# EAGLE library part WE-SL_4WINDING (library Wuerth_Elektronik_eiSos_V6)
SMD Common-Mode Choke Line Filter WE-SL For distortion-free removal of noise from transmitted electrical signals - 2 or 4 winding configuration - Offering a wide band width with the core materials of NiZn and MnZn -- Current compensated choke for data and signal lines -- USB/CAN/ISDN-Bus -- Power supply systems -- Control lines -- LAN, PBX, cable TV, CD-ROM, 8mm video, etc.

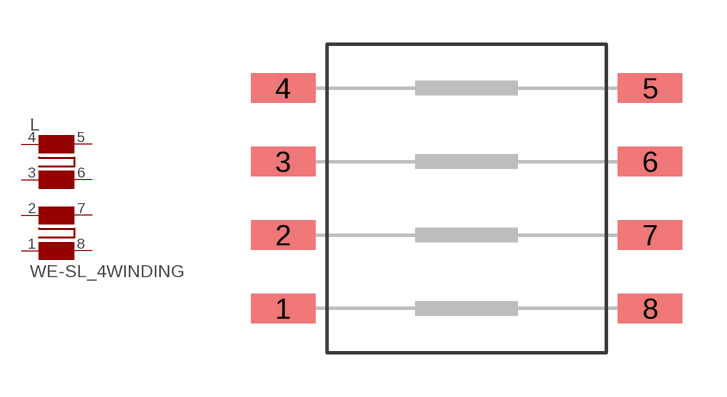
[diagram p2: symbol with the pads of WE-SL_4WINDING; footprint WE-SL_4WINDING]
Designator prefix L

## WE-SL_4WINDING  [WE-SL_4WINDING]
1  4  pas
2  3  pas
3  2  pas
4  1  pas
5  8  pas
6  7  pas
7  6  pas
8  5  pas

## Footprint WE-SL_4WINDING (pad centres in mm)
SMD Common-Mode Line Filter WE-SL
smd 2.2 x 1: 1 -6.25,-3.75; 2 -6.25,-1.25; 3 -6.25,1.25; 4 -6.25,3.75; 5 6.25,3.75; 6 6.25,1.25; 7 6.25,-1.25; 8 6.25,-3.75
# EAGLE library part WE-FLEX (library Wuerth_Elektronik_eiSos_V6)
FLEX-Transformer WE-FLEX Transformer with 6 windings - 4 sizes with 5 different lengths of air gap each - Insulation voltage 500 VDC - Low leakage inductance -- By using different circuits more than 300 transformer solutions and about 100 choke solution possible -- For all kinds of switching regulators: Flyback converters, Forward converters, Push- pull converters, SEPIC converter

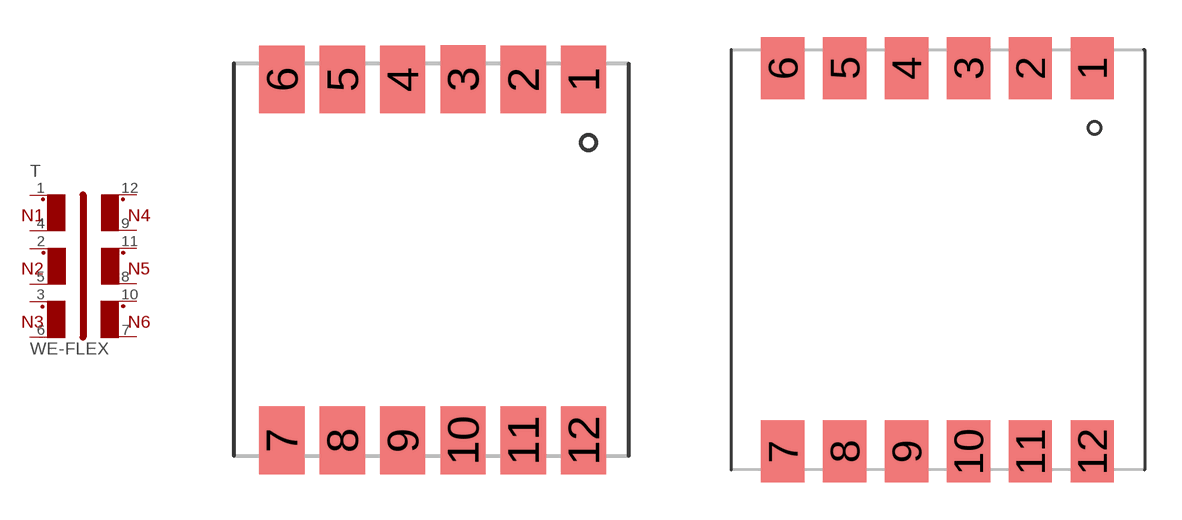
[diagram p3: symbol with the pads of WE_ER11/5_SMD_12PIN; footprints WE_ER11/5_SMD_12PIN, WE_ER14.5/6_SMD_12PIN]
Designator prefix T

## WE-FLEX_ER11/5  [WE_ER11/5_SMD_12PIN]
1  1  pas
2  3  pas
3  5  pas
4  2  pas
5  4  pas
6  6  pas
7  12  pas
8  10  pas
9  8  pas
10  11  pas
11  9  pas
12  7  pas

## WE-FLEX_ER14.5/6  [WE_ER14.5/6_SMD_12PIN]
Pads as for WE_ER11/5_SMD_12PIN

## WE-FLEX_EFD15  [WE_EFD15_SMD_12PIN]
1  1  pas
2  3  pas
3  5  pas
4  7  pas
5  9  pas
6  11  pas
7  12  pas
8  10  pas
9  8  pas
10  6  pas
11  4  pas
12  2  pas

## WE-FLEX_EFD20  [WE_EFD20_SMD_12PIN]
Pads as for WE_EFD15_SMD_12PIN

## Footprint WE_ER11/5_SMD_12PIN (pad centres in mm)
Transformer, ER11/5 SMD 12Pin
smd 1.5 x 2.25: 1 4.92,5.9; 2 2.92,5.9; 3 0.92,5.91; 4 -1.08,5.9; 5 -3.08,5.9; 6 -5.08,5.9; 7 -5.08,-6.07; 8 -3.08,-6.07; 9 -1.08,-6.07; 10 0.92,-6.07; 11 2.92,-6.07; 12 4.92,-6.07

## Footprint WE_ER14.5/6_SMD_12PIN (pad centres in mm)
Transformer, ER14.5/6 SMD 12Pin
smd 1.75 x 2.5: 1 6.26,7.75; 2 3.76,7.75; 3 1.26,7.75; 4 -1.24,7.75; 5 -3.74,7.75; 6 -6.24,7.75; 7 -6.24,-7.75; 8 -3.74,-7.75; 9 -1.24,-7.75; 10 1.26,-7.75; 11 3.76,-7.75; 12 6.26,-7.75

## Footprint WE_EFD15_SMD_12PIN (pad centres in mm)
Transformer, EFD15 SMD 12 Pin
smd 2.62 x 1.17: 1 -9.895,6.225; 2 -9.895,3.735; 3 -9.895,1.245; 4 -9.895,-1.245; 5 -9.895,-3.735; 6 -9.895,-6.225; 7 9.895,-6.225; 8 9.895,-3.735; 9 9.895,-1.245; 10 9.895,1.245; 11 9.895,3.735; 12 9.895,6.225

## Footprint WE_EFD20_SMD_12PIN (pad centres in mm)
Transformer, EFD20 SMD 12 Pin
smd 3.05 x 1.27: 1 -13.26,7.5; 2 -13.26,4.5; 3 -13.26,1.5; 4 -13.26,-1.5; 5 -13.26,-4.5; 6 -13.26,-7.5; 7 13.26,-7.5; 8 13.26,-4.5; 9 13.26,-1.5; 10 13.26,1.5; 11 13.26,4.5; 12 13.26,7.5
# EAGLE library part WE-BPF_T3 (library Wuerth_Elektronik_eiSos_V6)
SMD-Multilayer Chip Band-Pass Filter WE-BPF - low insertion loss - High attenuation - Guaranteed filter characteristics over a wide temperature range -- Rf applications in the frequency range up to 6GHz -- Wireless communcation systems like DECT, PACS, PHS, GSM,WLAN,Bluetooth,..

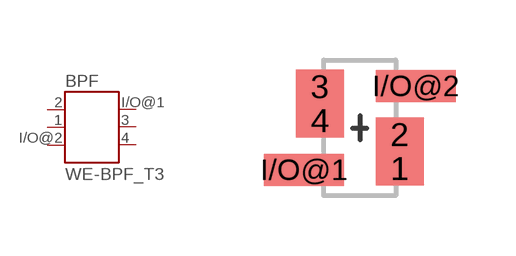
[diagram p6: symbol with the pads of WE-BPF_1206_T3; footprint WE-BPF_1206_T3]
Designator prefix BPF

## WE-BPF_T3_1206_T3  [WE-BPF_1206_T3]
1  GND  pas
2  GND  pas
3  GND  pas
4  GND  pas
I/O@1  I/O  pas
I/O@2  I/O  pas

## Footprint WE-BPF_1206_T3 (pad centres in mm)
Multilayer Chip Band -Pass Filter WE-BPF
smd 1.2 x 0.85: 1 1,-1.02; 2 1,-0.17; 3 -1,1.03; 4 -1,0.18
smd 2 x 0.8: I/O@1 -1.4,-1.05; I/O@2 1.4,1.05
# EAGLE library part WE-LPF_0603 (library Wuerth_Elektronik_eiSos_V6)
Multilayer Chip Low-Pass Filters WE-LPF SMD 0603 - One inductor and three capacitors or two inductors and five capacitors in one component - Power capacity up to 3W - Low insertion loss and high attenuation in the stop-band -- RF-applications in the area of 0.8 to 6 GHz -- wireless communication systems like DECT,PACS,PHS,GSM, Bluetooth,...

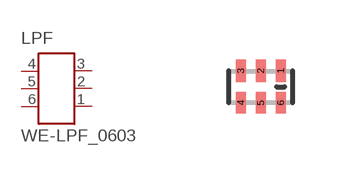
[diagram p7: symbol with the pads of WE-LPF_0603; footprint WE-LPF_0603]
Designator prefix LPF

## WE-LPF_0603  [WE-LPF_0603]
1  GND  pwr
2  NC  nc
3  GND  pwr
4  OUT  out
5  GND  pwr
6  IN  in

## Footprint WE-LPF_0603 (pad centres in mm)
Multilayer Chip Low-Pass Filters WE-LPF
smd 0.25 x 0.55: 1 0.5,0.4; 2 0,0.4; 3 -0.5,0.4; 4 -0.5,-0.4; 5 0,-0.4; 6 0.5,-0.4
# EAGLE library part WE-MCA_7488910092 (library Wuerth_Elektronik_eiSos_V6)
Multilayer Chip Antenna WE-MCA - SMD Multilayer Chip Antenna - Extremely low profile - Very light component - Operating temperature: -40°C to +85°C - Power capacity: 3 W max. - Omni-directional -- For RF application in the area of 2,4 GHz -- WLAN -- Home RF (868 MHz) -- Bluetooth applications -- IEEE 802.11a/b -- GPS -- GSM -- WIMAX applications

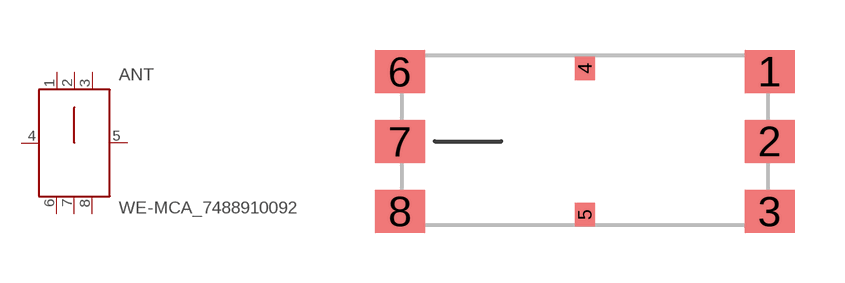
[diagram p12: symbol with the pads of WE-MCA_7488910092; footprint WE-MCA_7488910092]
Designator prefix ANT

## WE-MCA_7488910092  [WE-MCA_7488910092]
1  NC  nc
2  FD  pas
3  NC  nc
4  NC  nc
5  NC  nc
6  NC  nc
7  NC  nc
8  NC  nc

## Footprint WE-MCA_7488910092 (pad centres in mm)
Multilayer Chip Antenna WE-MCA
smd 1.5 x 1.3: 1 5.55,2.1; 2 5.55,0; 3 5.55,-2.1; 6 -5.55,2.1; 7 -5.55,0; 8 -5.55,-2.1
smd 0.6 x 0.7: 4 0,2.2; 5 0,-2.2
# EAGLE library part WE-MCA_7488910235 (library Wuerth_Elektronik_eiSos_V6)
Multilayer Chip Antenna WE-MCA - SMD Multilayer Chip Antenna - Extremely low profile - Very light component - Operating temperature: -40°C to +85°C - Power capacity: 3 W max. - Omni-directional -- For RF application in the area of 2,4 GHz -- WLAN -- Home RF (868 MHz) -- Bluetooth applications -- IEEE 802.11a/b -- GPS -- GSM -- WIMAX applications

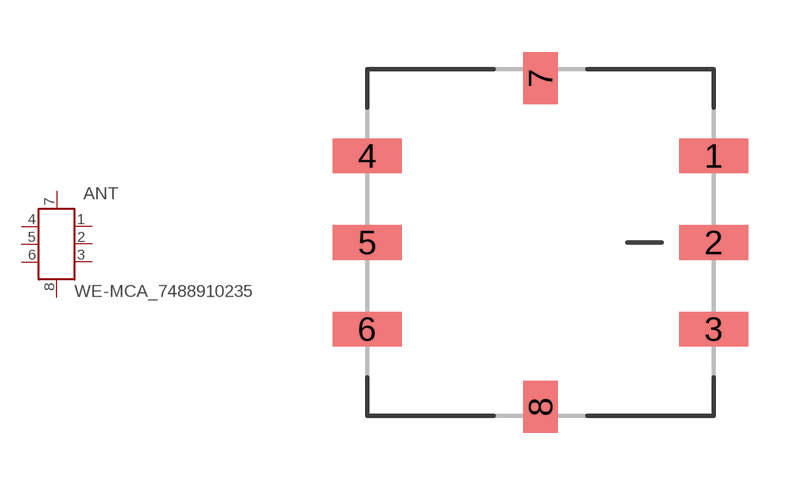
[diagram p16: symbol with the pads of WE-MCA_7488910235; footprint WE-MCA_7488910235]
Designator prefix ANT

## WE-MCA_7488910235  [WE-MCA_7488910235]
1  GND  pwr
2  FD  pas
3  GND  pwr
4  NC  nc
5  NC  nc
6  NC  nc
7  NC  nc
8  NC  nc

## Footprint WE-MCA_7488910235 (pad centres in mm)
Multilayer Chip Antenna WE-MCA
smd 2 x 1: 1 5,2.5; 2 5,0; 3 5,-2.5; 4 -5,2.5; 5 -5,0; 6 -5,-2.5
smd 1 x 1.5: 7 0,4.75; 8 0,-4.75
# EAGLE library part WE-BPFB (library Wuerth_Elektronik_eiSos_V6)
Multilayer SMD Band-Pass Filter with Balun WE-BPFB - Low insertion loss - High attenuation in the stop zone - Impedance ration 50:100 - Power capacity: 1 W max. - Operating temperature: -40°C up to +85°C -- 2,4 GHz WLAN -- Home RF -- Bluetooth

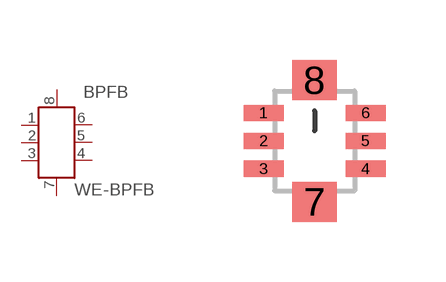
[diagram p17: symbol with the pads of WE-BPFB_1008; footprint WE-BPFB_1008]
Designator prefix BPFB

## WE-BPFB_1008  [WE-BPFB_1008]
1  NC  nc
2  UNBAL.P  pas
3  NC/DC  pas
4  BAL.P  pas
5  NC  nc
6  BAL.P  pas
7  GND  pas
8  GND  pas

## Footprint WE-BPFB_1008 (pad centres in mm)
Multilayer SMD Band-Pass Filter with Balun WE-BPFB
smd 1 x 0.4: 1 -1.275,0.7; 2 -1.275,0; 3 -1.275,-0.7; 4 1.275,-0.7; 5 1.275,0; 6 1.275,0.7
smd 1.1 x 1: 7 0,-1.525; 8 0,1.525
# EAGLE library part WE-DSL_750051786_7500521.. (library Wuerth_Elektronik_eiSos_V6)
SMD-ADSL Transformer WE-DSL - IEC60950 compatible -- for ADSL applications -- Matched to various manufacturers ADSL ICs

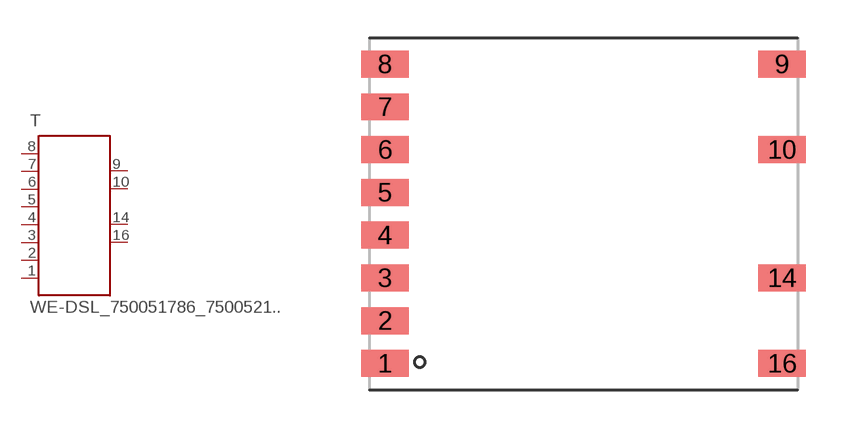
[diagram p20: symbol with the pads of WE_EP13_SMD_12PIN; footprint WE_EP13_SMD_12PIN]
Designator prefix T

## WE-DSL_750051786_7500521..  [WE_EP13_SMD_12PIN]
1  1  pas
2  2  pas
3  3  pas
4  4  pas
5  5  pas
6  6  pas
7  7  pas
8  8  pas
9  9  pas
10  10  pas
14  11  pas
16  12  pas

## Footprint WE_EP13_SMD_12PIN (pad centres in mm)
Transformer, EP13 SMD 12 Pin
smd 1.88 x 1.07: 1 -7.885,-5.95; 2 -7.885,-4.25; 3 -7.885,-2.55; 4 -7.885,-0.85; 5 -7.885,0.85; 6 -7.885,2.55; 7 -7.885,4.25; 8 -7.885,5.95; 9 7.885,5.95; 10 7.885,2.55; 14 7.885,-2.55; 16 7.885,-5.95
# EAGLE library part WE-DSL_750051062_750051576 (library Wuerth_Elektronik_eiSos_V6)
SMD-HDSL Transformer WE-DSL - IEC60950 compatible -- for HDSL applications -- Matched to various manufacturers HDSL ICs

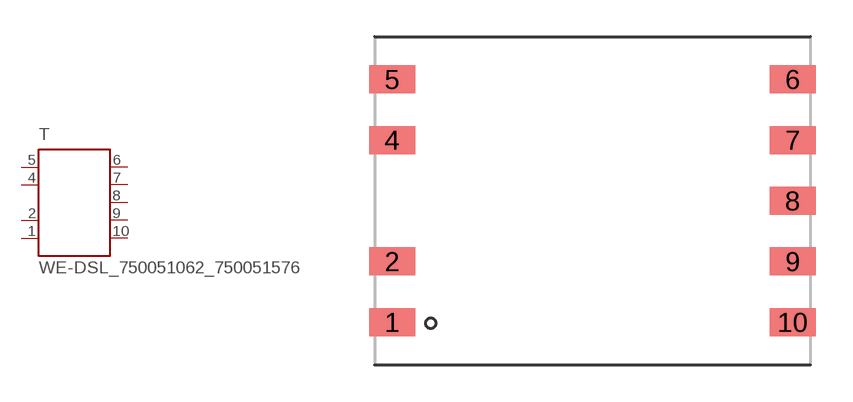
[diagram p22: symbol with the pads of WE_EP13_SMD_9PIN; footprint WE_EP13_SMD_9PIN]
Designator prefix T

## WE-DSL_750051062_750051576  [WE_EP13_SMD_9PIN]
1  1  pas
2  2  pas
4  4  pas
5  5  pas
6  6  pas
7  7  pas
8  8  pas
9  9  pas
10  10  pas

## Footprint WE_EP13_SMD_9PIN (pad centres in mm)
SMD-xDSL Transformer WE-DSL
smd 1.88 x 1.143: 1 -8.18,-4.96; 2 -8.18,-2.48; 4 -8.18,2.48; 5 -8.18,4.96; 6 8.18,4.96; 7 8.18,2.48; 8 8.18,0; 9 8.18,-2.48; 10 8.18,-4.96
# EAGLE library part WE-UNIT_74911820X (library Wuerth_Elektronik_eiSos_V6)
Off-Line Transformer WE-Unit - Nominal input voltage: 85-265 VAC - Output power 9 W - Operating temperature: -40°C to +125 °C - Clearance and creepage distance 6 mm min. - Isolation voltage 4 kVAC -- Designed for Tiny switch ICs from power integration and NCP101x or 105x of Semiconductor -- Universal input -- Offline-switch mode power supplies

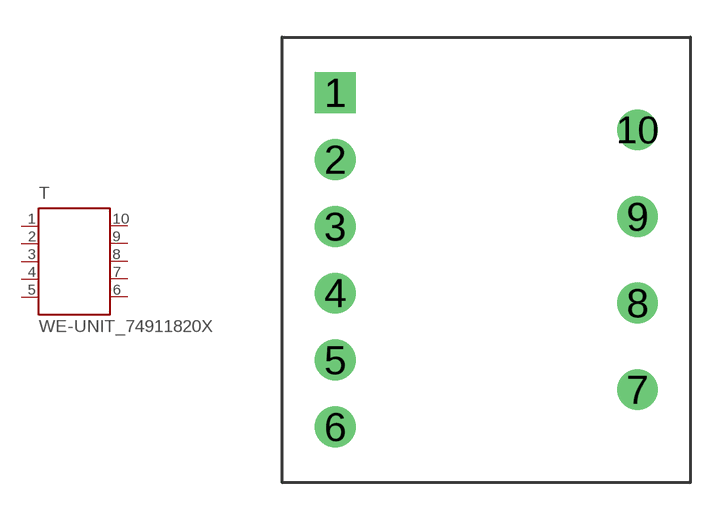
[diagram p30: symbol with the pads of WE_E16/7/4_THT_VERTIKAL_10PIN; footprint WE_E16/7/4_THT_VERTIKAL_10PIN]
Designator prefix T

## WE-UNIT_74911820X  [WE_E16/7/4_THT_VERTIKAL_10PIN]
1  1  pas
2  2  pas
3  3  pas
4  4  pas
5  5  pas
6  6  pas
7  7  pas
8  8  pas
9  9  pas
10  10  pas

## Footprint WE_E16/7/4_THT_VERTIKAL_10PIN (pad centres in mm)
Transformer, E16/7/4 THT Vertikal 10 Pin
drill 1.1 square: 1 -6.1,6.75
drill 1.1: 2 -6.1,4.05; 3 -6.1,1.35; 4 -6.1,-1.35; 5 -6.1,-4.05; 6 -6.1,-6.75; 7 6.1,-5.25; 8 6.1,-1.75; 9 6.1,1.75; 10 6.1,5.25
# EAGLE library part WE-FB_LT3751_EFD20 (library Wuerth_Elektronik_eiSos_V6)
Flyback Converter WE-FB for LT3751 - designd for LT3751

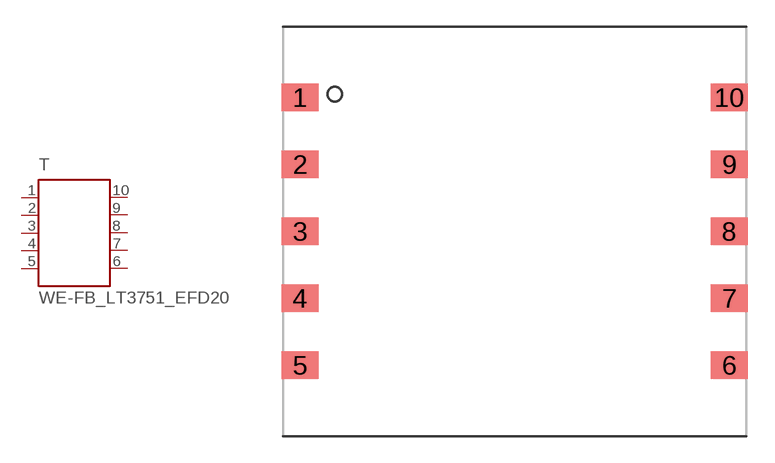
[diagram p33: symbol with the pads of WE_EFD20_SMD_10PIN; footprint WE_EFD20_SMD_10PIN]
Designator prefix T

## WE-FB_LT3751_EFD20  [WE_EFD20_SMD_10PIN]
1  1  pas
2  2  pas
3  3  pas
4  4  pas
5  5  pas
6  6  pas
7  7  pas
8  8  pas
9  9  pas
10  10  pas

## Footprint WE_EFD20_SMD_10PIN (pad centres in mm)
Transformer, EFD20 SMD 10 Pin
smd 2.08 x 1.55: 1 -12.05,7.52; 2 -12.05,3.76; 3 -12.05,0; 4 -12.05,-3.76; 5 -12.05,-7.52; 6 12.05,-7.52; 7 12.05,-3.76; 8 12.05,0; 9 12.05,3.76; 10 12.05,7.52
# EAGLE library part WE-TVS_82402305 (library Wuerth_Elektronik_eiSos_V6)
TVS Diode Array WE-TVS, Standard Series - Low capazity - No leakage current - Low clamping voltage - high ESD voltage protection - Uni- and bidirectional protection -- DC Distribution -- Headsets and Accessoires -- PDAs -- Digital Cameras -- MP3-Players -- Touch Panels

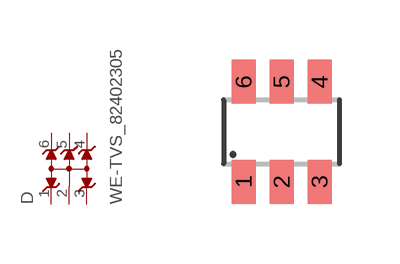
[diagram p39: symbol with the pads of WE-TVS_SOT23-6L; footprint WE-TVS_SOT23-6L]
Designator prefix D

## WE-TVS_82402305  [WE-TVS_SOT23-6L]
1  1  pas
2  GND  pwr
3  2  pas
4  3  pas
5  4  pas
6  5  pas

## Footprint WE-TVS_SOT23-6L (pad centres in mm)
TVS Diode Array WE-TVS
smd 0.6 x 1.1: 1 -0.95,-1.25; 2 0,-1.25; 3 0.95,-1.25; 4 0.95,1.25; 5 0,1.25; 6 -0.95,1.25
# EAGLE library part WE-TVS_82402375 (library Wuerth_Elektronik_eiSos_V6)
TVS Diode Array WE-TVS, Standard Series - Low capazity - No leakage current - Low clamping voltage - high ESD voltage protection - Uni- and bidirectional protection -- DC Distribution -- Headsets and Accessoires -- PDAs -- Digital Cameras -- MP3-Players -- Touch Panels

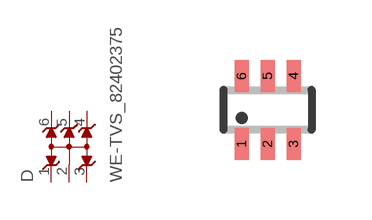
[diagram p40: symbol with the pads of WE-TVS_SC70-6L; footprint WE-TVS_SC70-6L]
Designator prefix D

## WE-TVS_82402375  [WE-TVS_SC70-6L]
1  1  pas
2  GND  pwr
3  2  pas
4  3  pas
5  4  pas
6  5  pas

## Footprint WE-TVS_SC70-6L (pad centres in mm)
TVS Diode Array WE-TVS
smd 0.35 x 0.8: 1 -0.65,-0.85; 2 0,-0.85; 3 0.65,-0.85; 4 0.65,0.85; 5 0,0.85; 6 -0.65,0.85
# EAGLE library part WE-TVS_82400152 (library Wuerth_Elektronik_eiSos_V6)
TVS Diode Array WE-TVS, High Speed Series - Low capazity - No leakage current - Low clamping voltage - high ESD voltage protection -- USB 1.0 - 2.0 Flow Thru Design

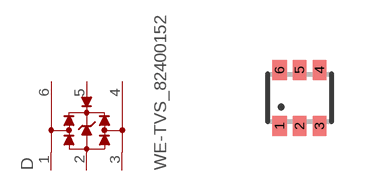
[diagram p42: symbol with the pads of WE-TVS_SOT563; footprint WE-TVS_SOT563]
Designator prefix D

## WE-TVS_82400152  [WE-TVS_SOT563]
1  1  pas
2  GND  pwr
3  2  pas
4  3  pas
5  VDD  pwr
6  4  pas

## Footprint WE-TVS_SOT563 (pad centres in mm)
TVS Diode Array WE-TVS
smd 0.35 x 0.5: 1 -0.5,-0.7; 2 0,-0.7; 3 0.5,-0.7; 4 0.5,0.7; 5 0,0.7; 6 -0.5,0.7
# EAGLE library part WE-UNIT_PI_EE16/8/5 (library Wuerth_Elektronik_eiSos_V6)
Off-Line Transformer WE-Unit PI - Nominal input voltage: 85-265 VAC - Output power from 2 W to 5 W - Operating temperature: -40°C to +125 °C - Clearance and creepage distance 6 mm min. - Isolation voltage 4 kVAC -- Especially designed for several ICs from Power Integrations -- Universal input -- Offline-switch mode power supplies

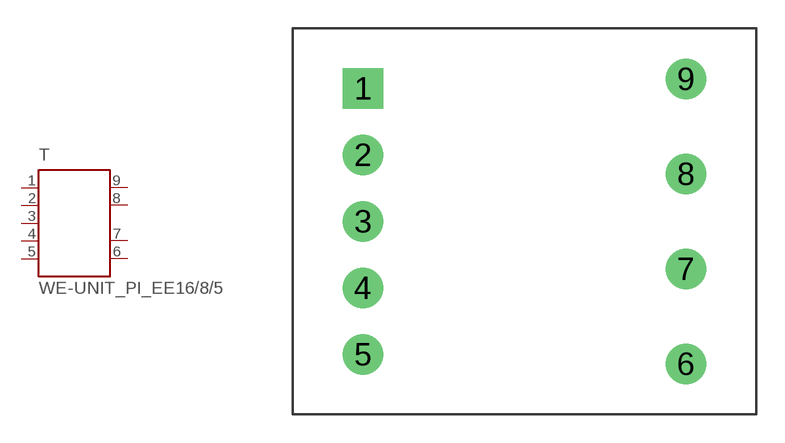
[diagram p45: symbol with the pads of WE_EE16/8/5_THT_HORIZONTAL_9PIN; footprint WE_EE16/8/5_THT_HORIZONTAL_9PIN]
Designator prefix T

## WE-UNIT_PI_EE16/8/5  [WE_EE16/8/5_THT_HORIZONTAL_9PIN]
1  5  pas
2  4  pas
3  3  pas
4  2  pas
5  1  pas
6  9  pas
7  8  pas
8  7  pas
9  6  pas

## Footprint WE_EE16/8/5_THT_HORIZONTAL_9PIN (pad centres in mm)
Transformer, EE16/8/5 THT Horizontal 9 Pin
drill 1.42 square: 1 -8.5,7
drill 1.42: 2 -8.5,3.5; 3 -8.5,0; 4 -8.5,-3.5; 5 -8.5,-7; 6 8.5,-7.5; 7 8.5,-2.5; 8 8.5,2.5; 9 8.5,7.5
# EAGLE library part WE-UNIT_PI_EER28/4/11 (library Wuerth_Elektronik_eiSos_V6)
Off-Line Transformer WE-Unit PI - Nominal input voltage: 85-265 VAC - Output power 34.4 W - Operating temperature: -40°C to +125 °C - Clearance and creepage distance 6 mm min. - Isolation voltage 4 kVAC -- Especially designed for several ICs from Power Integrations TOP258 -- Universal input -- Offline-switch mode power supplies

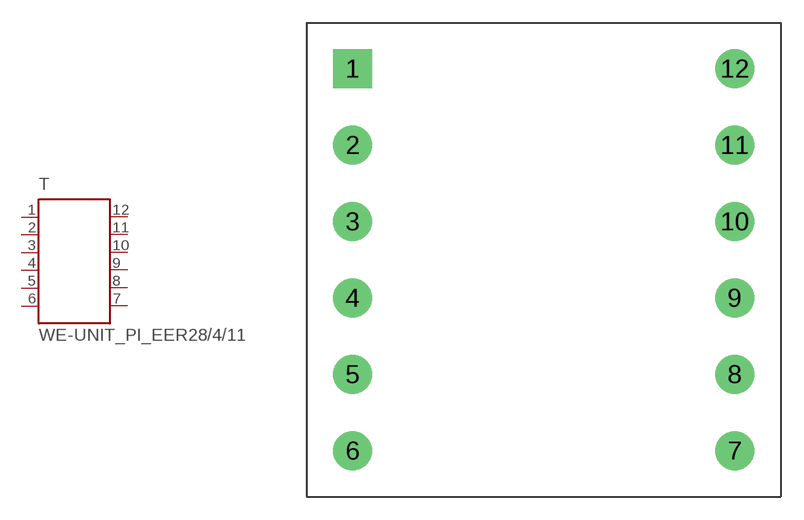
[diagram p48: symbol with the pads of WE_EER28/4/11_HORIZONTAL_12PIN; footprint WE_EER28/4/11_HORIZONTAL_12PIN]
Designator prefix T

## WE-UNIT_PI_EER28/4/11  [WE_EER28/4/11_HORIZONTAL_12PIN]
1  1  pas
2  2  pas
3  3  pas
4  4  pas
5  5  pas
6  6  pas
7  7  pas
8  8  pas
9  9  pas
10  10  pas
11  11  pas
12  12  pas

## Footprint WE_EER28/4/11_HORIZONTAL_12PIN (pad centres in mm)
Transformer, EER 28/4/11 THT Horizontal 12Pin
drill 1.69 square: 1 -12.5,12.5
drill 1.69: 2 -12.5,7.5; 3 -12.5,2.5; 4 -12.5,-2.5; 5 -12.5,-7.5; 6 -12.5,-12.5; 7 12.5,-12.5; 8 12.5,-7.5; 9 12.5,-2.5; 10 12.5,2.5; 11 12.5,7.5; 12 12.5,12.5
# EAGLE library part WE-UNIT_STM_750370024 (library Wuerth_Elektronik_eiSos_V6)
Off-Line Transformer WE-Unit STM - Nominal input voltage: 85-265 VAC - Operating temperature: -40°C to +125 °C - Isolation voltage 4 kVAC -- Especially designed for several ICs from STMicroelectronics VIPer 17H -- Universal input -- Offline-switch mode power supplies

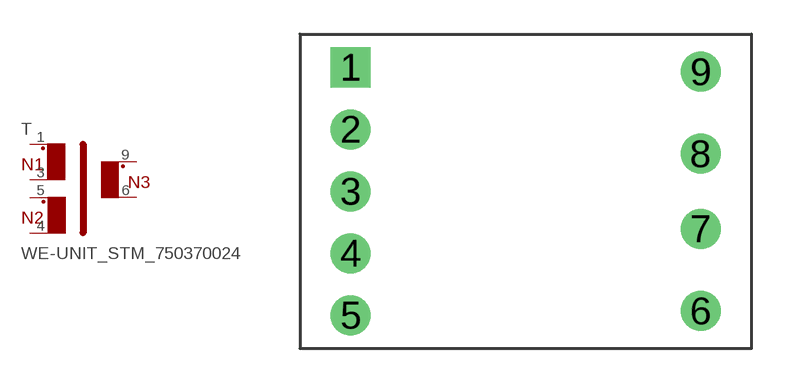
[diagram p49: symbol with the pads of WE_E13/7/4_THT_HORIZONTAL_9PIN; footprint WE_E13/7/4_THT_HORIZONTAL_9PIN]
Designator prefix T

## WE-UNIT_STM_750370024  [WE_E13/7/4_THT_HORIZONTAL_9PIN]
1  1  pas
3  2  pas
4  4  pas
5  3  pas
6  5  pas
9  6  pas

## Footprint WE_E13/7/4_THT_HORIZONTAL_9PIN (pad centres in mm)
Transformer, E13/7/4 THT Horizontal 9 Pin
drill 1.17 square: 1 -7.675,5.44
drill 1.17: 2 -7.675,2.72; 3 -7.675,0; 4 -7.675,-2.72; 5 -7.675,-5.44; 6 7.675,-5.25; 7 7.675,-1.65; 8 7.675,1.65; 9 7.675,5.25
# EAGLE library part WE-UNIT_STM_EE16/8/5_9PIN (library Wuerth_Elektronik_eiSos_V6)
Off-Line Transformer WE-Unit STM - Nominal input voltage: 85-265 VAC - Operating temperature: -40°C to +125 °C - Isolation voltage 4 kVAC -- Especially designed for several ICs from STMicroelectronics VIPer 17L and VIPer 15L -- Universal input -- Offline-switch mode power supplies

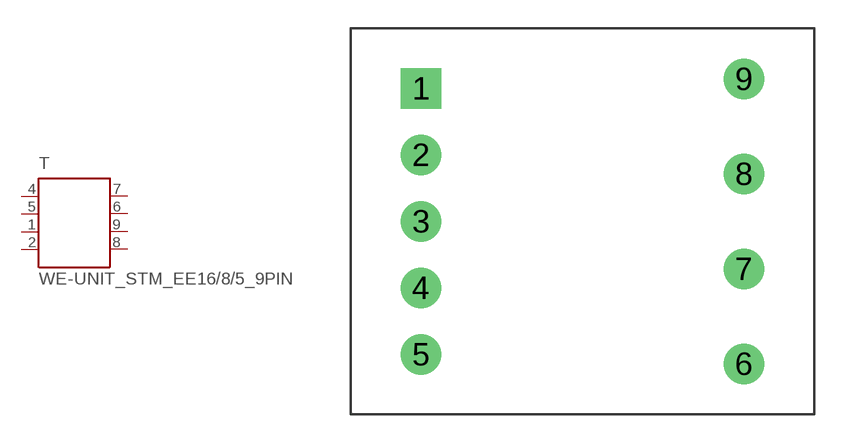
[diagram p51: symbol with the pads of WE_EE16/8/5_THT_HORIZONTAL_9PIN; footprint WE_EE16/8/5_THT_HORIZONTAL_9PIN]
Designator prefix T

## WE-UNIT_STM_EE16/8/5_9PIN  [WE_EE16/8/5_THT_HORIZONTAL_9PIN]
1  2  pas
2  1  pas
4  4  pas
5  3  pas
6  6  pas
7  5  pas
8  8  pas
9  7  pas

## Footprint WE_EE16/8/5_THT_HORIZONTAL_9PIN (pad centres in mm)
Transformer, EE16/8/5 THT Horizontal 9 Pin
drill 1.42 square: 1 -8.5,7
drill 1.42: 2 -8.5,3.5; 3 -8.5,0; 4 -8.5,-3.5; 5 -8.5,-7; 6 8.5,-7.5; 7 8.5,-2.5; 8 8.5,2.5; 9 8.5,7.5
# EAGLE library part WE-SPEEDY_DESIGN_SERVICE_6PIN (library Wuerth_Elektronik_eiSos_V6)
WE-Speedy Design Service, 6 Pin - Any application that fits package style - Switch Mode Power: Flyback, Forward, Push-Pull, Coupled Inductor -- Telecom Applications: xDSL, POTS Splitter Inductors

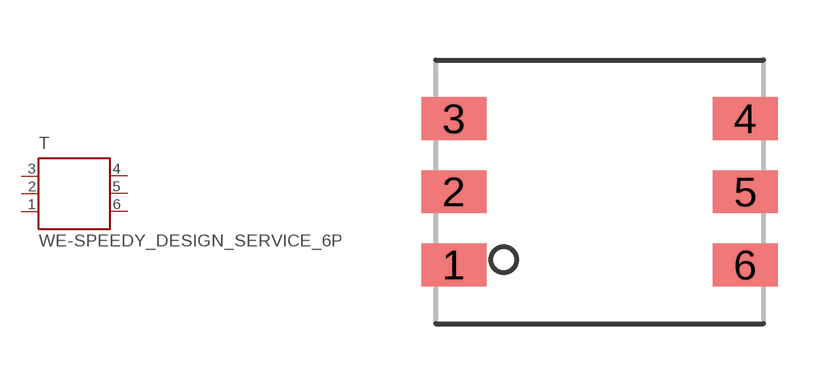
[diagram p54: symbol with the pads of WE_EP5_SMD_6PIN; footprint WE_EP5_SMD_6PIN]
Designator prefix T

## WE-SPEEDY_DESIGN_SERVICE_6PIN  [WE_EP5_SMD_6PIN]
1  1  pas
2  2  pas
3  3  pas
4  4  pas
5  5  pas
6  6  pas

## Footprint WE_EP5_SMD_6PIN (pad centres in mm)
Transformer, EP5 SMD 6 Pin
smd 1.63 x 1.07: 1 -3.645,-1.83; 2 -3.645,0; 3 -3.645,1.83; 4 3.645,1.83; 5 3.645,0; 6 3.645,-1.83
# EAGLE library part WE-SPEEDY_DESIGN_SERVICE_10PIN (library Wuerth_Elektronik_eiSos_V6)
WE-Speedy Design Service, 10 Pin - Any application that fits package style - Switch Mode Power: Flyback, Forward, Push-Pull, Coupled Inductor -- Telecom Applications: xDSL, POTS Splitter Inductors

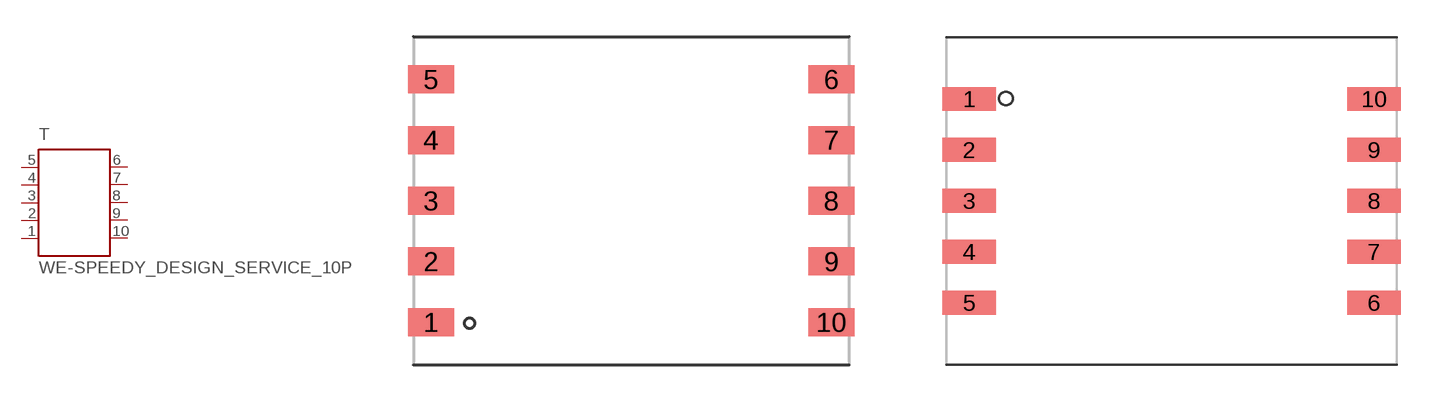
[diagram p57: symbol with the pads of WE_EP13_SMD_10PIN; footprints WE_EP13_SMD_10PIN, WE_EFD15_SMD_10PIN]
Designator prefix T

## WE-SPEEDY_DESIGN_SERVICE_10PIN_EP13_SMD  [WE_EP13_SMD_10PIN]
1  5  pas
2  4  pas
3  3  pas
4  2  pas
5  1  pas
6  10  pas
7  9  pas
8  8  pas
9  7  pas
10  6  pas

## WE-SPEEDY_DESIGN_SERVICE_10PIN_EFD15_SMD  [WE_EFD15_SMD_10PIN]
1  1  pas
2  2  pas
3  3  pas
4  4  pas
5  5  pas
6  6  pas
7  7  pas
8  8  pas
9  9  pas
10  10  pas

## WE-SPEEDY_DESIGN_SERVICE_10PIN_EFD20_SMD  [WE_EFD20_SMD_10PIN]
Pads as for WE_EFD15_SMD_10PIN

## WE-SPEEDY_DESIGN_SERVICE_10PIN_EE16/7/4_THT  [WE_EE16/7/4_THT_HORIZONTAL_10PIN]
Pads as for WE_EFD15_SMD_10PIN

## WE-SPEEDY_DESIGN_SERVICE_10PIN_EE16/7/4_THT_VERTICAL  [WE_E16/7/4_THT_VERTIKAL_10PIN]
Pads as for WE_EFD15_SMD_10PIN

## WE-SPEEDY_DESIGN_SERVICE_10PIN_EE20/10/6_THT  [WE_EE20/10/6_THT_HORIZONTAL_10PIN]
Pads as for WE_EFD15_SMD_10PIN

## WE-SPEEDY_DESIGN_SERVICE_10PIN_EE25/13/7_THT  [WE_EE25/13/7_THT_HORIZONTAL_10PIN]
Pads as for WE_EFD15_SMD_10PIN

## WE-SPEEDY_DESIGN_SERVICE_10PIN_EE25/13/7_THT_VERTICAL  [WE_EE25/13/7_THT_VERTICAL_10PIN]
Pads as for WE_EFD15_SMD_10PIN

## Footprint WE_EP13_SMD_10PIN (pad centres in mm)
Transformer, EP13 SMD 10 Pin
smd 1.88 x 1.143: 1 -8.18,-4.96; 2 -8.18,-2.48; 3 -8.18,0; 4 -8.18,2.48; 5 -8.18,4.96; 6 8.18,4.96; 7 8.18,2.48; 8 8.18,0; 9 8.18,-2.48; 10 8.18,-4.96

## Footprint WE_EFD15_SMD_10PIN (pad centres in mm)
Transformer, EFD15 SMD 10 Pin
smd 2.62 x 1.17: 1 -9.895,4.98; 2 -9.895,2.49; 3 -9.895,0; 4 -9.895,-2.49; 5 -9.895,-4.98; 6 9.895,-4.98; 7 9.895,-2.49; 8 9.895,0; 9 9.895,2.49; 10 9.895,4.98

## Footprint WE_EFD20_SMD_10PIN (pad centres in mm)
Transformer, EFD20 SMD 10 Pin
smd 2.08 x 1.55: 1 -12.05,7.52; 2 -12.05,3.76; 3 -12.05,0; 4 -12.05,-3.76; 5 -12.05,-7.52; 6 12.05,-7.52; 7 12.05,-3.76; 8 12.05,0; 9 12.05,3.76; 10 12.05,7.52

## Footprint WE_EE16/7/4_THT_HORIZONTAL_10PIN (pad centres in mm)
Transformer, EE16/7/4 THT Horizontal 10 Pin
drill 1.17 square: 1 -7.75,6.4
drill 1.17: 2 -7.75,3.2; 3 -7.75,0; 4 -7.75,-3.2; 5 -7.75,-6.4; 6 7.75,-6.4; 7 7.75,-3.2; 8 7.75,0; 9 7.75,3.2; 10 7.75,6.4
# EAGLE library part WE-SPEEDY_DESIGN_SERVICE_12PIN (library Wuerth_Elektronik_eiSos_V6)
WE-Speedy Design Service, 12 Pin - Any application that fits package style - Switch Mode Power: Flyback, Forward, Push-Pull, Coupled Inductor -- Telecom Applications: xDSL, POTS Splitter Inductors

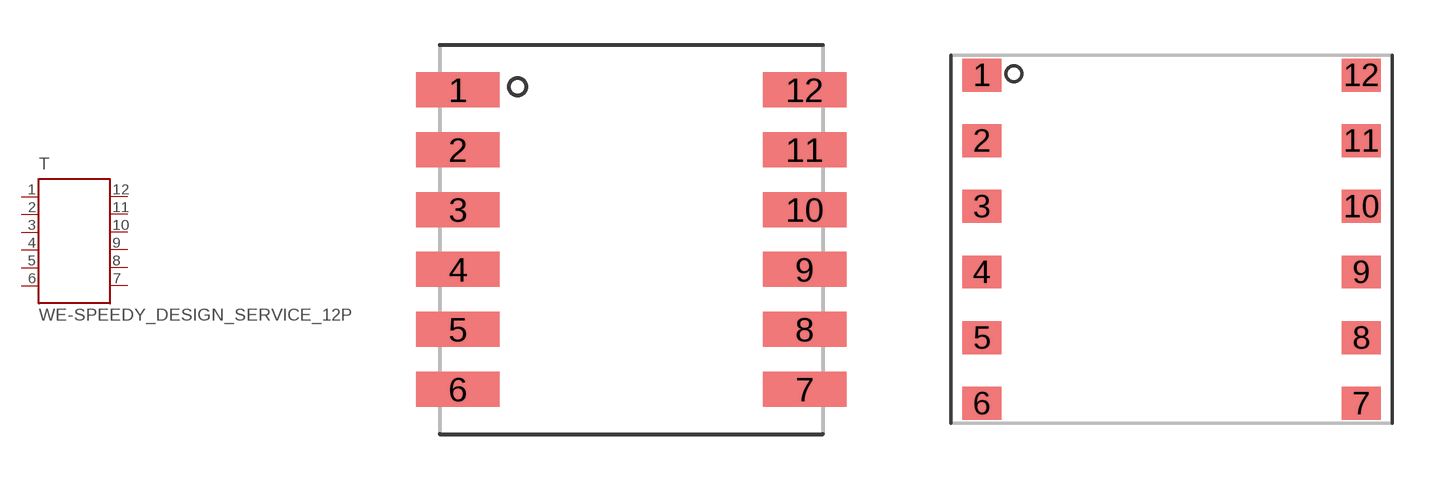
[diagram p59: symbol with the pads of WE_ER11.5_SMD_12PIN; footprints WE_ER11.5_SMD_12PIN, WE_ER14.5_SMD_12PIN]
Designator prefix T

## WE-SPEEDY_DESIGN_SERVICE_12PIN_ER11.5_SMD  [WE_ER11.5_SMD_12PIN]
1  1  pas
2  2  pas
3  3  pas
4  4  pas
5  5  pas
6  6  pas
7  7  pas
8  8  pas
9  9  pas
10  10  pas
11  11  pas
12  12  pas

## WE-SPEEDY_DESIGN_SERVICE_12PIN_ER14.5_SMD  [WE_ER14.5_SMD_12PIN]
Pads as for WE_ER11.5_SMD_12PIN

## WE-SPEEDY_DESIGN_SERVICE_12PIN_EFD15_SMD  [WE_EFD15_SMD_12PIN]
Pads as for WE_ER11.5_SMD_12PIN

## WE-SPEEDY_DESIGN_SERVICE_12PIN_EFD20_SMD  [WE_EFD20_SMD_12PIN]
Pads as for WE_ER11.5_SMD_12PIN

## WE-SPEEDY_DESIGN_SERVICE_12PIN_EFD25_SMD  [WE_EFD25_SMD_12PIN]
Pads as for WE_ER11.5_SMD_12PIN

## WE-SPEEDY_DESIGN_SERVICE_12PIN_ER28_THT  [WE_ER28_THT_HORIZONTAL_12PIN]
Pads as for WE_ER11.5_SMD_12PIN

## Footprint WE_ER11.5_SMD_12PIN (pad centres in mm)
Transformer, ER11.5 SMD 12 Pin
smd 2.79 x 1.17: 1 -5.79,5; 2 -5.79,3; 3 -5.79,1; 4 -5.79,-1; 5 -5.79,-3; 6 -5.79,-5; 7 5.79,-5; 8 5.79,-3; 9 5.79,-1; 10 5.79,1; 11 5.79,3; 12 5.79,5

## Footprint WE_ER14.5_SMD_12PIN (pad centres in mm)
Transformer, ER14.5 SMD 12 Pin
smd 1.5 x 1.25: 1 -7.225,6.25; 2 -7.225,3.75; 3 -7.225,1.25; 4 -7.225,-1.25; 5 -7.225,-3.75; 6 -7.225,-6.25; 7 7.225,-6.25; 8 7.225,-3.75; 9 7.225,-1.25; 10 7.225,1.25; 11 7.225,3.75; 12 7.225,6.25

## Footprint WE_EFD15_SMD_12PIN (pad centres in mm)
Transformer, EFD15 SMD 12 Pin
smd 2.62 x 1.17: 1 -9.895,6.225; 2 -9.895,3.735; 3 -9.895,1.245; 4 -9.895,-1.245; 5 -9.895,-3.735; 6 -9.895,-6.225; 7 9.895,-6.225; 8 9.895,-3.735; 9 9.895,-1.245; 10 9.895,1.245; 11 9.895,3.735; 12 9.895,6.225

## Footprint WE_EFD20_SMD_12PIN (pad centres in mm)
Transformer, EFD20 SMD 12 Pin
smd 3.05 x 1.27: 1 -13.26,7.5; 2 -13.26,4.5; 3 -13.26,1.5; 4 -13.26,-1.5; 5 -13.26,-4.5; 6 -13.26,-7.5; 7 13.26,-7.5; 8 13.26,-4.5; 9 13.26,-1.5; 10 13.26,1.5; 11 13.26,4.5; 12 13.26,7.5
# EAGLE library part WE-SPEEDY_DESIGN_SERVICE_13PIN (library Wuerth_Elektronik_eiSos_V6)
WE-Speedy Design Service, 13 Pin - Any application that fits package style - Switch Mode Power: Flyback, Forward, Push-Pull, Coupled Inductor -- Telecom Applications: xDSL, POTS Splitter Inductors

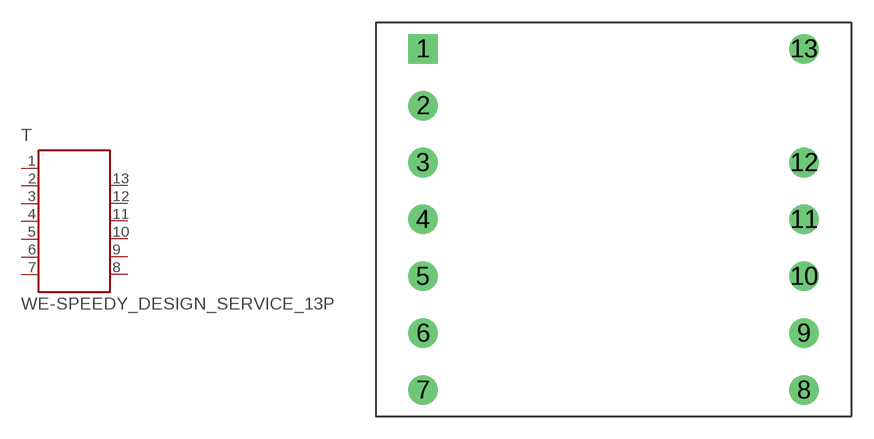
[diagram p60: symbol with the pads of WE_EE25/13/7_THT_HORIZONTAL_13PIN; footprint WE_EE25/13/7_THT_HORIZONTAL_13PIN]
Designator prefix T

## WE-SPEEDY_DESIGN_SERVICE_13PIN_EE25/13/7_THT  [WE_EE25/13/7_THT_HORIZONTAL_13PIN]
1  1  pas
2  2  pas
3  3  pas
4  4  pas
5  5  pas
6  6  pas
7  7  pas
8  8  pas
9  9  pas
10  10  pas
11  11  pas
12  12  pas
13  13  pas

## Footprint WE_EE25/13/7_THT_HORIZONTAL_13PIN (pad centres in mm)
Transformer, EE25/13/7 THT Horizontal 13 Pin
drill 1.32 square: 1 -12.75,11.43
drill 1.32: 2 -12.75,7.62; 3 -12.75,3.81; 4 -12.75,0; 5 -12.75,-3.81; 6 -12.75,-7.62; 7 -12.75,-11.43; 8 12.75,-11.43; 9 12.75,-7.62; 10 12.75,-3.81; 11 12.75,0; 12 12.75,3.81; 13 12.75,11.43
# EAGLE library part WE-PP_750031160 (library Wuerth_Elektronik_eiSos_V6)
WE-PP 750034460 - L= 500µH - Turns ration 1:2.7 -- for LTC1535/MAX3535

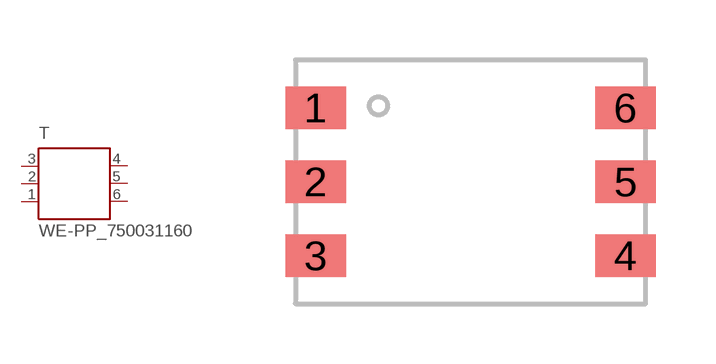
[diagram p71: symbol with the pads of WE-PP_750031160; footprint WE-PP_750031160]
Designator prefix T

## WE-PP_750031160  [WE-PP_750031160]
1  1  pas
2  2  pas
3  3  pas
4  4  pas
5  5  pas
6  6  pas

## Footprint WE-PP_750031160 (pad centres in mm)
WE-PP 750034460 - L= 500µH - Turns ration 1:2.7 -- for LTC1535/MAX3535
smd 1.52 x 1.07: 1 -3.875,1.85; 2 -3.875,0; 3 -3.875,-1.85; 4 3.875,-1.85; 5 3.875,0; 6 3.875,1.85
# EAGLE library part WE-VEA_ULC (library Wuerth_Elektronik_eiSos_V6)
ESD Suppressor-Array WE-VEA ULC - Fast response time (1 ns) - Low signal insertion loss - No leakage current - Low clamping voltage - Almost no energy consumption in stand-by mode - Excellent absorption for ESD-impulses -- Protection data lines -- Protection of bus systems -- Protection of video transmission lines -- Protection of semiconductors -- ESD protection in accordance with EN 61000-4-2

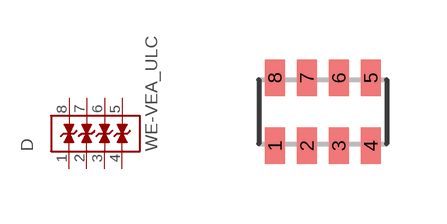
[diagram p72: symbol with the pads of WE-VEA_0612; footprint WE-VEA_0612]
Designator prefix D

## WE-VEA_ULC_0612  [WE-VEA_0612]
1  1  pas
2  2  pas
3  3  pas
4  4  pas
5  5  pas
6  6  pas
7  7  pas
8  8  pas

## Footprint WE-VEA_0612 (pad centres in mm)
WESURGE ESD Suppressor-Array WE-VEA
smd 0.5 x 0.9: 1 -1.2,-0.85; 2 -0.4,-0.85; 3 0.4,-0.85; 4 1.2,-0.85; 5 1.2,0.85; 6 0.4,0.85; 7 -0.4,0.85; 8 -1.2,0.85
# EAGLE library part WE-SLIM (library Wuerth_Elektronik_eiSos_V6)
Slim-Transformer WE-SLIM - total hight 12.0 mm max. - height 8.0 mm above PCB - output power 65W -- offline switch mode power supplies -- TV -- devices with heigh issues

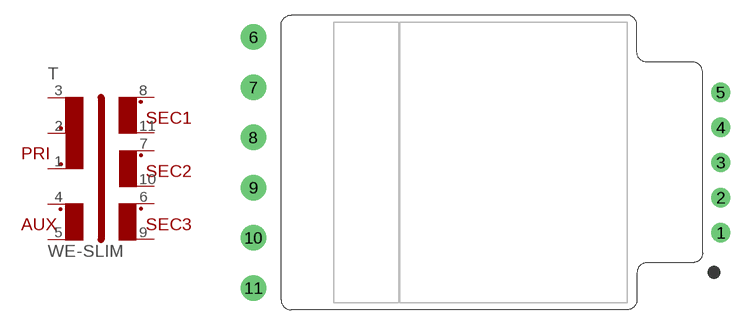
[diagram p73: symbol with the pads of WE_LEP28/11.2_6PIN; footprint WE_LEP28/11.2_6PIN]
Designator prefix T

## WE-SLIM  [WE_LEP28/11.2_6PIN]
1  1  pas
2  2  pas
3  3  pas
4  4  pas
5  5  pas
6  6  pas
7  7  pas
8  8  pas
9  9  pas
10  10  pas
11  11  pas

## Footprint WE_LEP28/11.2_6PIN (pad centres in mm)
Slim-Transformer WE-SLIM
drill 1.1 pad 1.93: 1 23.645,-7; 2 23.645,-3.5; 3 23.645,0; 4 23.645,3.5; 5 23.645,7
drill 1.5 pad 2.54: 6 -22.89,12.5; 7 -22.89,7.5; 8 -22.89,2.5; 9 -22.89,-2.5; 10 -22.89,-7.5; 11 -22.89,-12.5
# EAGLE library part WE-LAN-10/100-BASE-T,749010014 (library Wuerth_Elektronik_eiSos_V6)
LAN-Transformer WE-LAN 10/100 Base T - Compliant with IEEE 802.3 standards - SMD -- Ethernet -- Power over Ethernet -- 1 Gigabit Ethernet -- Compliant with most IC's for ethernet applications like Intel, AMD, Globespan and Realtek -- Hub, Router, Switch

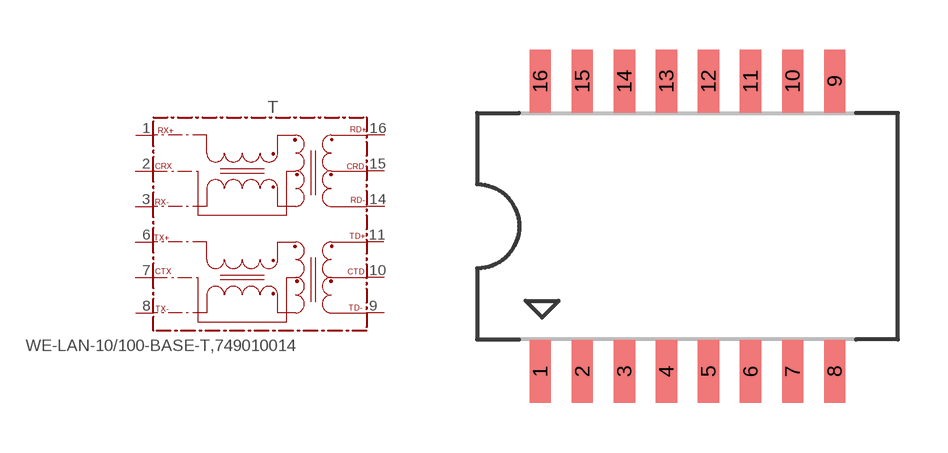
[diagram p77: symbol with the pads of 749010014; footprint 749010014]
Designator prefix T

## WE-LAN-10/100-BASE-T,749010014 (COMPANY-URL: http://www.we-online.de; CREATED-BY: Christin Zierenner; CREATED-DATE: June 2012; DATASHEET-URL: http://katalog.we-online.de/kataloge/eisos/media/pdf/749010014.pdf; MANUFACTURER: Würth Elektronik eiSos GmbH)  [749010014]
1  RX+
2  CRX
3  RX-
6  TX+
7  CTX
8  TX-
9  TD-
10  CTD
11  TD+
14  RD-
15  CRD
16  RD+

## Footprint 749010014 (pad centres in mm)
MAX Height =5.08mm
smd 0.64 x 1.91: 1 -4.445,-4.385; 2 -3.175,-4.385; 3 -1.905,-4.385; 4 -0.635,-4.385; 5 0.635,-4.385; 6 1.905,-4.385; 7 3.175,-4.385; 8 4.445,-4.385; 9 4.445,4.385; 10 3.175,4.385; 11 1.905,4.385; 12 0.635,4.385; 13 -0.635,4.385; 14 -1.905,4.385; 15 -3.175,4.385; 16 -4.445,4.385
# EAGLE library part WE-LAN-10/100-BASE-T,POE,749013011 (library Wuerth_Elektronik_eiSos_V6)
LAN-Transformer WE-LAN 10/100 Base Tx - Compliant with IEEE 802.3 standards - SMD -- Ethernet -- Power over Ethernet -- 1 Gigabit Ethernet -- Compliant with most IC's for ethernet applications like Intel, AMD, Globespan and Realtek -- Hub, Router, Switch

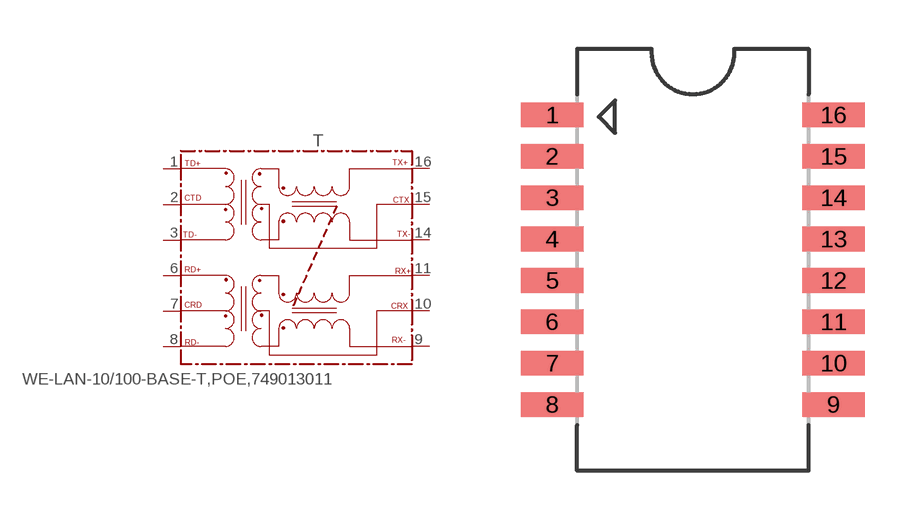
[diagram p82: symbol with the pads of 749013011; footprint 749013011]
Designator prefix T

## WE-LAN-10/100-BASE-T,POE,749013011 (COMPANY-URL: http://www.we-online.de; CREATED-BY: Christin Zierenner; CREATED-DATE: June 2012; DATASHEET-URL: http://katalog.we-online.de/kataloge/eisos/media/pdf/749013011.pdf; MANUFACTURER: Würth Elektronik eiSos GmbH)  [749013011]
1  TD+
2  CTD
3  TD-
6  RD+
7  CRD
8  RD-
9  RX-
10  CRX
11  RX+
14  TX-
15  CTX
16  TX+

## Footprint 749013011 (pad centres in mm)
MAX Height = 5.33mm
smd 1.91 x 0.76: 1 -4.317,4.445; 2 -4.317,3.175; 3 -4.317,1.905; 4 -4.317,0.635; 5 -4.317,-0.635; 6 -4.317,-1.905; 7 -4.317,-3.175; 8 -4.317,-4.445; 9 4.317,-4.445; 10 4.317,-3.175; 11 4.317,-1.905; 12 4.317,-0.635; 13 4.317,0.635; 14 4.317,1.905; 15 4.317,3.175; 16 4.317,4.445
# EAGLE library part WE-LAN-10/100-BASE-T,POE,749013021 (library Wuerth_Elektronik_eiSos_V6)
LAN-Transformer WE-LAN 10/100 Base Tx - Compliant with IEEE 802.3 standards - SMD -- Ethernet -- Power over Ethernet -- 1 Gigabit Ethernet -- Compliant with most IC's for ethernet applications like Intel, AMD, Globespan and Realtek -- Hub, Router, Switch

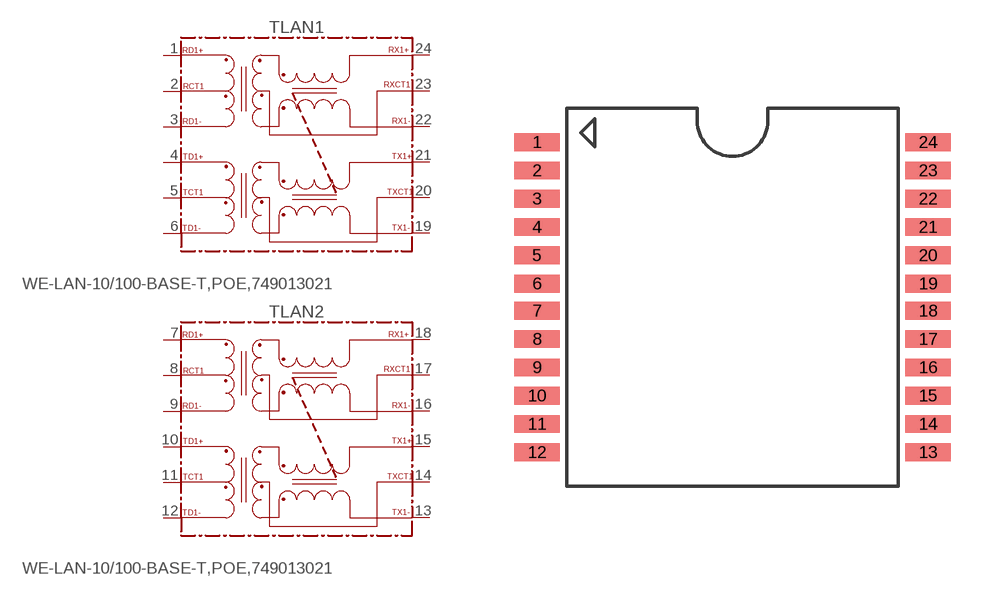
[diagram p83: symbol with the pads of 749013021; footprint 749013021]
Designator prefix T; gates LAN1=749013021 LAN2=749013021

## WE-LAN-10/100-BASE-T,POE,749013021 (COMPANY-URL: http://www.we-online.de; CREATED-BY: Christin Zierenner; CREATED-DATE: June 2012; DATASHEET-URL: http://katalog.we-online.de/kataloge/eisos/media/pdf/749013021.pdf; MANUFACTURER: Würth Elektronik eiSos GmbH)  [749013021]
1  LAN1:RD1+
2  LAN1:RCT1
3  LAN1:RD1-
4  LAN1:TD1+
5  LAN1:TCT1
6  LAN1:TD1-
7  LAN2:RD1+
8  LAN2:RCT1
9  LAN2:RD1-
10  LAN2:TD1+
11  LAN2:TCT1
12  LAN2:TD1-
13  LAN2:TX1-
14  LAN2:TXCT1
15  LAN2:TX1+
16  LAN2:RX1-
17  LAN2:RXCT1
18  LAN2:RX1+
19  LAN1:TX1-
20  LAN1:TXCT1
21  LAN1:TX1+
22  LAN1:RX1-
23  LAN1:RXCT1
24  LAN1:RX1+

## Footprint 749013021 (pad centres in mm)
MAX Height = 6.22mm
smd 1.65 x 0.64: 1 -7.05,5.59; 2 -7.05,4.57; 3 -7.05,3.55; 4 -7.05,2.53; 5 -7.05,1.51; 6 -7.05,0.49; 7 -7.05,-0.49; 8 -7.05,-1.51; 9 -7.05,-2.53; 10 -7.05,-3.55; 11 -7.05,-4.57; 12 -7.05,-5.59; 13 7.05,-5.59; 14 7.05,-4.57; 15 7.05,-3.55; 16 7.05,-2.53; 17 7.05,-1.51; 18 7.05,-0.49; 19 7.05,0.49; 20 7.05,1.51; 21 7.05,2.53; 22 7.05,3.55; 23 7.05,4.57; 24 7.05,5.59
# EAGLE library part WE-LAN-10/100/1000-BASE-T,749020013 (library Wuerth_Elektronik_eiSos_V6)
LAN-Transformer WE-LAN 10/100/1000 Base Tx - Compliant with IEEE 802.3 standards - SMD -- Ethernet -- Power over Ethernet -- 1 Gigabit Ethernet -- Compliant with most IC's for ethernet applications like Intel, AMD, Globespan and Realtek -- Hub, Router, Switch

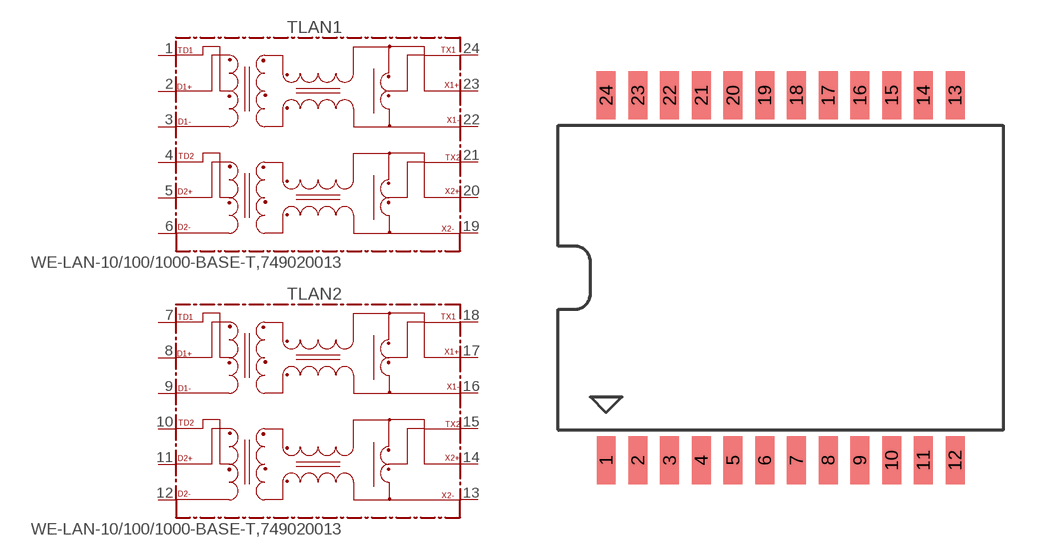
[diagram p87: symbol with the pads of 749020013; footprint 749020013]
Designator prefix T; gates LAN1=749020013 LAN2=749020013

## WE-LAN-10/100/1000-BASE-T,749020013 (COMPANY-URL: http://www.we-online.de; CREATED-BY: Christin Zierenner; CREATED-DATE: June 2012; DATASHEET-URL: http://katalog.we-online.de/kataloge/eisos/media/pdf/749020013.pdf; MANUFACTURER: Würth Elektronik eiSos GmbH)  [749020013]
1  LAN1:TD1
2  LAN1:D1+
3  LAN1:D1-
4  LAN1:TD2
5  LAN1:D2+
6  LAN1:D2-
7  LAN2:TD1
8  LAN2:D1+
9  LAN2:D1-
10  LAN2:TD2
11  LAN2:D2+
12  LAN2:D2-
13  LAN2:X2-
14  LAN2:X2+
15  LAN2:TX2
16  LAN2:X1-
17  LAN2:X1+
18  LAN2:TX1
19  LAN1:X2-
20  LAN1:X2+
21  LAN1:TX2
22  LAN1:X1-
23  LAN1:X1+
24  LAN1:TX1

## Footprint 749020013 (pad centres in mm)
MAX Height =5.84 mm
smd 0.76 x 1.905: 1 -6.985,-7.303; 2 -5.715,-7.303; 3 -4.445,-7.303; 4 -3.175,-7.303; 5 -1.905,-7.303; 6 -0.635,-7.303; 7 0.635,-7.303; 8 1.905,-7.303; 9 3.175,-7.303; 10 4.445,-7.303; 11 5.715,-7.303; 12 6.985,-7.303; 13 6.985,7.303; 14 5.715,7.303; 15 4.445,7.303; 16 3.175,7.303; 17 1.905,7.303; 18 0.635,7.303; 19 -0.635,7.303; 20 -1.905,7.303; 21 -3.175,7.303; 22 -4.445,7.303; 23 -5.715,7.303; 24 -6.985,7.303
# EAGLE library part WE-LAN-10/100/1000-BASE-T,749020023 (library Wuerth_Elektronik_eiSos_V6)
LAN-Transformer WE-LAN 10/100/1000 Base Tx - Compliant with IEEE 802.3 standards - SMD -- Ethernet -- Power over Ethernet -- 1 Gigabit Ethernet -- Compliant with most IC's for ethernet applications like Intel, AMD, Globespan and Realtek -- Hub, Router, Switch

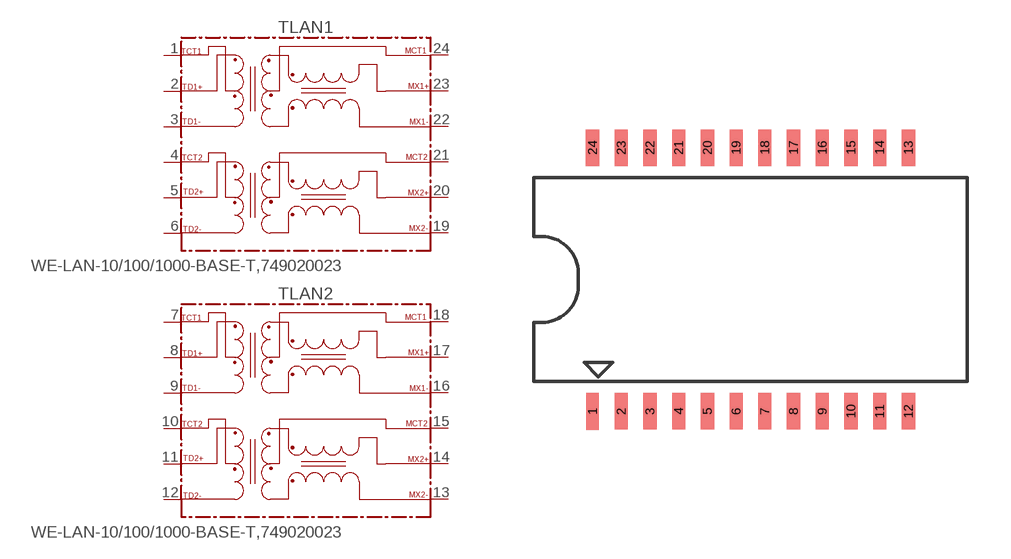
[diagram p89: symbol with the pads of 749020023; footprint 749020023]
Designator prefix T; gates LAN1=749020023 LAN2=749020023

## WE-LAN-10/100/1000-BASE-T,749020023 (COMPANY-URL: http://www.we-online.de; CREATED-BY: Christin Zierenner; CREATED-DATE: June 2012; DATASHEET-URL: http://katalog.we-online.de/kataloge/eisos/media/pdf/749020023.pdf; MANUFACTURER: Würth Elektronik eiSos GmbH)  [749020023]
1  LAN1:TCT1
2  LAN1:TD1+
3  LAN1:TD1-
4  LAN1:TCT2
5  LAN1:TD2+
6  LAN1:TD2-
7  LAN2:TCT1
8  LAN2:TD1+
9  LAN2:TD1-
10  LAN2:TCT2
11  LAN2:TD2+
12  LAN2:TD2-
13  LAN2:MX2-
14  LAN2:MX2+
15  LAN2:MCT2
16  LAN2:MX1-
17  LAN2:MX1+
18  LAN2:MCT1
19  LAN1:MX2-
20  LAN1:MX2+
21  LAN1:MCT2
22  LAN1:MX1-
23  LAN1:MX1+
24  LAN1:MCT1

## Footprint 749020023 (pad centres in mm)
MAX Height = 4mm
smd 0.46 x 1.27: 1 -5.5,-4.595; 2 -4.5,-4.595; 3 -3.5,-4.595; 4 -2.5,-4.595; 5 -1.5,-4.595; 6 -0.5,-4.595; 7 0.5,-4.595; 8 1.5,-4.595; 9 2.5,-4.595; 10 3.5,-4.595; 11 4.5,-4.595; 12 5.5,-4.595; 13 5.5,4.595; 14 4.5,4.595; 15 3.5,4.595; 16 2.5,4.595; 17 1.5,4.595; 18 0.5,4.595; 19 -0.5,4.595; 20 -1.5,4.595; 21 -2.5,4.595; 22 -3.5,4.595; 23 -4.5,4.595; 24 -5.5,4.595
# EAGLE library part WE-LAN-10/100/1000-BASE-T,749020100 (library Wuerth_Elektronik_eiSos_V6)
LAN-Transformer WE-LAN 10/10/1000 Base Tx - Compliant with IEEE 802.3 standards - SMD -- Ethernet -- Power over Ethernet -- 1 Gigabit Ethernet -- Compliant with most IC's for ethernet applications like Intel, AMD, Globespan and Realtek -- Hub, Router, Switch

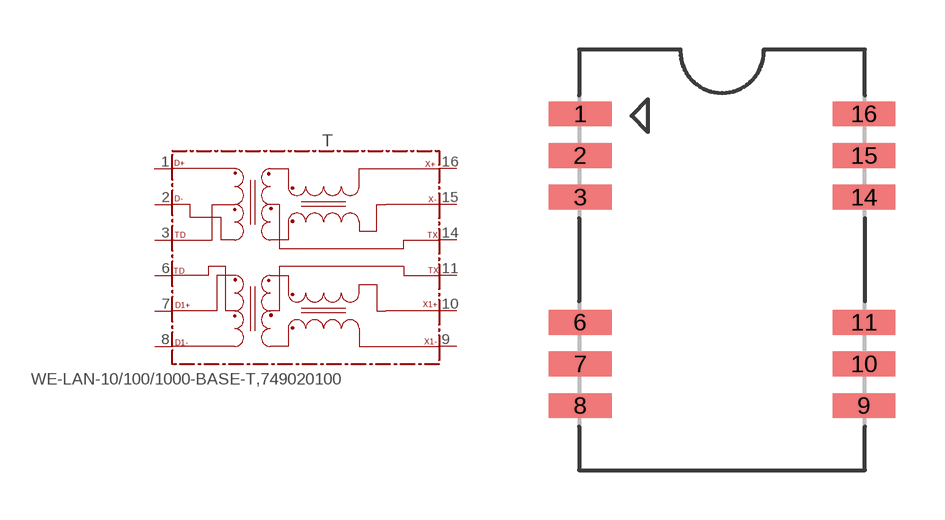
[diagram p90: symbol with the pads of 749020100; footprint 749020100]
Designator prefix T

## WE-LAN-10/100/1000-BASE-T,749020100 (COMPANY-URL: http://www.we-online.de; CREATED-BY: Christin Zierenner; CREATED-DATE: June 2012; DATASHEET-URL: http://katalog.we-online.de/kataloge/eisos/media/pdf/749020100.pdf; MANUFACTURER: Würth Elektronik eiSos GmbH)  [749020100]
1  D+
2  D-
3  TD1
6  TD2
7  D1+
8  D1-
9  X1-
10  X1+
11  TX1
14  TX
15  X-
16  X+

## Footprint 749020100 (pad centres in mm)
MAX Height = 2.16mm
smd 1.91 x 0.76: 1 -4.32,4.445; 2 -4.32,3.175; 3 -4.32,1.905; 6 -4.32,-1.905; 7 -4.32,-3.175; 8 -4.32,-4.445; 9 4.32,-4.445; 10 4.32,-3.175; 11 4.32,-1.905; 14 4.32,1.905; 15 4.32,3.175; 16 4.32,4.445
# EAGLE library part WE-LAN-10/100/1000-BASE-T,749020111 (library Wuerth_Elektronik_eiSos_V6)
LAN-Transformer WE-LAN 10/10/1000 Base Tx - Compliant with IEEE 802.3 standards - SMD -- Ethernet -- Power over Ethernet -- 1 Gigabit Ethernet -- Compliant with most IC's for ethernet applications like Intel, AMD, Globespan and Realtek -- Hub, Router, Switch

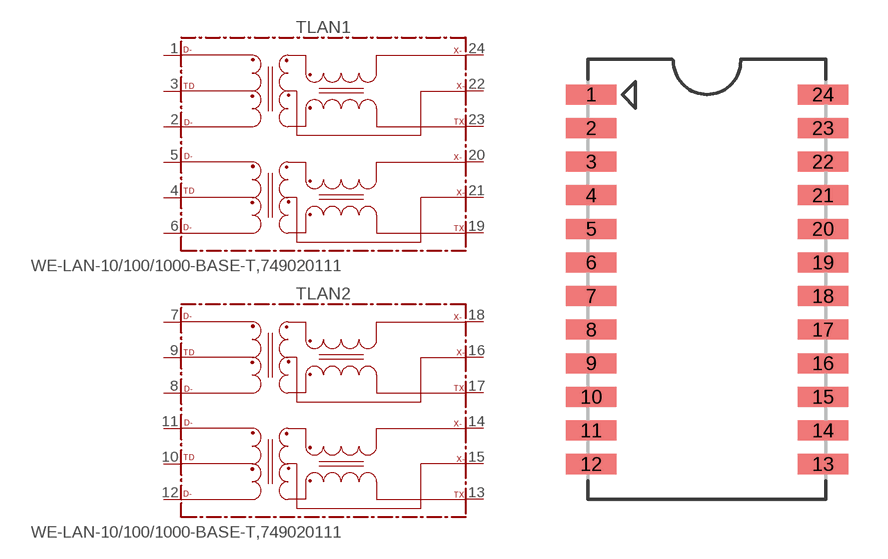
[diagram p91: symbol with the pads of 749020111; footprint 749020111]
Designator prefix T; gates LAN1=749020111 LAN2=749020111

## WE-LAN-10/100/1000-BASE-T,749020111 (COMPANY-URL: http://www.we-online.de; CREATED-BY: Christin Zierenner; CREATED-DATE: June 2012; DATASHEET-URL: http://katalog.we-online.de/kataloge/eisos/media/pdf/749020111.pdf; MANUFACTURER: Würth Elektronik eiSos GmbH)  [749020111]
1  LAN1:D1-
2  LAN1:D1A-
3  LAN1:TD1
4  LAN1:TD2
5  LAN1:D2-
6  LAN1:D2A-
7  LAN2:D1-
8  LAN2:D1A-
9  LAN2:TD1
10  LAN2:TD2
11  LAN2:D2-
12  LAN2:D2A-
13  LAN2:X2A-
14  LAN2:X2-
15  LAN2:TX2
16  LAN2:TX1
17  LAN2:X1A-
18  LAN2:X1-
19  LAN1:X2A-
20  LAN1:X2-
21  LAN1:TX2
22  LAN1:TX1
23  LAN1:X1A-
24  LAN1:X1-

## Footprint 749020111 (pad centres in mm)
MAX Height =2.16mm
smd 1.91 x 0.76: 1 -4.38,6.985; 2 -4.38,5.715; 3 -4.38,4.445; 4 -4.38,3.175; 5 -4.38,1.905; 6 -4.38,0.635; 7 -4.38,-0.635; 8 -4.38,-1.905; 9 -4.38,-3.175; 10 -4.38,-4.445; 11 -4.38,-5.715; 12 -4.38,-6.985; 13 4.38,-6.985; 14 4.38,-5.715; 15 4.38,-4.445; 16 4.38,-3.175; 17 4.38,-1.905; 18 4.38,-0.635; 19 4.38,0.635; 20 4.38,1.905; 21 4.38,3.175; 22 4.38,4.445; 23 4.38,5.715; 24 4.38,6.985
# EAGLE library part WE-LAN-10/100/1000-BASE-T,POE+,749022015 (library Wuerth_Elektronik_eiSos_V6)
LAN-Transformer WE-LAN 10/10/1000 Base Tx - Compliant with IEEE 802.3 standards - SMD -- Ethernet -- Power over Ethernet -- 1 Gigabit Ethernet -- Compliant with most IC's for ethernet applications like Intel, AMD, Globespan and Realtek -- Hub, Router, Switch

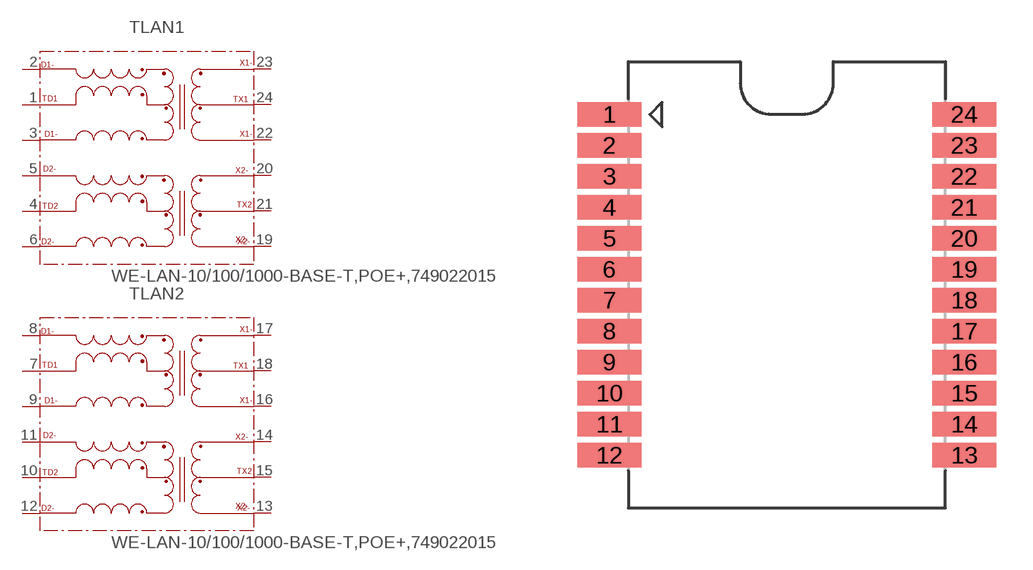
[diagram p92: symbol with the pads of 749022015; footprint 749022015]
Designator prefix T; gates LAN1=749022015 LAN2=749022015

## WE-LAN-10/100/1000-BASE-T,POE+,749022015 (COMPANY-URL: http://www.we-online.de; CREATED-BY: Christin Zierenner; CREATED-DATE: June 2012; DATASHEET-URL: http://katalog.we-online.de/kataloge/eisos/media/pdf/749022015.pdf; MANUFACTURER: Würth Elektronik eiSos GmbH)  [749022015]
1  LAN1:TD1
2  LAN1:D1-
3  LAN1:D1A-
4  LAN1:TD2
5  LAN1:D2-
6  LAN1:D2A-
7  LAN2:TD1
8  LAN2:D1-
9  LAN2:D1A-
10  LAN2:TD2
11  LAN2:D2-
12  LAN2:D2A-
13  LAN2:X2A-
14  LAN2:X2-
15  LAN2:TX2
16  LAN2:X1A-
17  LAN2:X1-
18  LAN2:TX1
19  LAN1:X2A-
20  LAN1:X2-
21  LAN1:TX2
22  LAN1:X1A-
23  LAN1:X1-
24  LAN1:TX1

## Footprint 749022015 (pad centres in mm)
MAX Height = 10.26 mm
smd 2.62 x 1.01: 1 -7.265,6.98; 2 -7.265,5.71; 3 -7.265,4.44; 4 -7.265,3.17; 5 -7.265,1.9; 6 -7.265,0.63; 7 -7.265,-0.63; 8 -7.265,-1.9; 9 -7.265,-3.17; 10 -7.265,-4.44; 11 -7.265,-5.71; 12 -7.265,-6.98; 13 7.265,-6.98; 14 7.265,-5.71; 15 7.265,-4.44; 16 7.265,-3.17; 17 7.265,-1.9; 18 7.265,-0.63; 19 7.265,0.63; 20 7.265,1.9; 21 7.265,3.17; 22 7.265,4.44; 23 7.265,5.71; 24 7.265,6.98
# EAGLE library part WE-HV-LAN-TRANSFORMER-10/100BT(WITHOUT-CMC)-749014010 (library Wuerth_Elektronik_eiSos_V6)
WE-LAN HV LAN-Transformer Characteristics: •Compliant with IEEE802.3 and 802.3af standards •Operating temperature: 0 °C to +70 °C •SMD •4 kV Hipot test Applications: •Ethernet •Compliant with most IC's for Ethernet applications like Intel, AMD, Conexant, Realtek, etc. •Hub, Router, Switches, medical applications

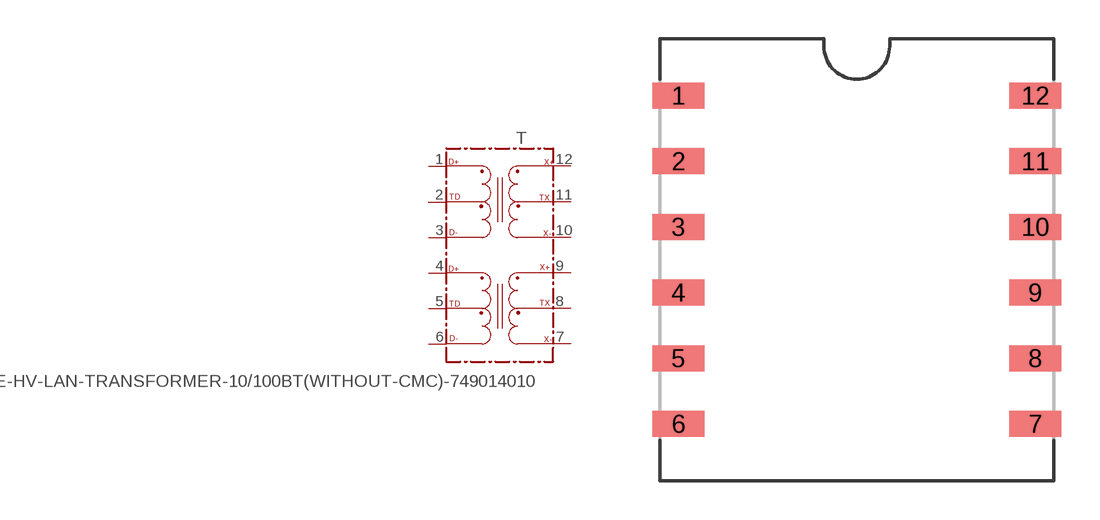
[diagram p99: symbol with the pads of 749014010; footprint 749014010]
Designator prefix T

## WE-HV-LAN-TRANSFORMER-10/100BT(WITHOUT-CMC)-749014010 (COMPANY-URL: http://www.we-online.de; CREATED-BY: Christin Zierenner; CREATED-DATE: July 2012; DATASHEET-URL: http://katalog.we-online.de/kataloge/eisos/media/pdf/749014010.pdf; MANUFACTURER: Würth Elektronik eiSos GmbH)  [749014010]
1  D+
2  TD
3  D-
4  D1+
5  TD1
6  D1-
7  X1-
8  TX1
9  X1+
10  X-
11  TX
12  X+

## Footprint 749014010 (pad centres in mm)
MAX Height=8.40 mm
smd 2 x 1: 1 -6.9,6.35; 2 -6.9,3.81; 3 -6.9,1.27; 4 -6.9,-1.27; 5 -6.9,-3.81; 6 -6.9,-6.35; 7 6.9,-6.35; 8 6.9,-3.81; 9 6.9,-1.27; 10 6.9,1.27; 11 6.9,3.81; 12 6.9,6.35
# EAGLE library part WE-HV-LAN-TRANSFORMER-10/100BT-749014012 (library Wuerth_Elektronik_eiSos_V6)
WE-LAN HV LAN-Transformer Characteristics: •Compliant with IEEE802.3 and 802.3af standards •Operating temperature: 0 °C to +70 °C •SMD •6 kV Hipot test Applications: •Ethernet •Compliant with most IC's for Ethernet applications like Intel, AMD, Conexant, Realtek, etc. •Hub, Router, Switches, medical applications

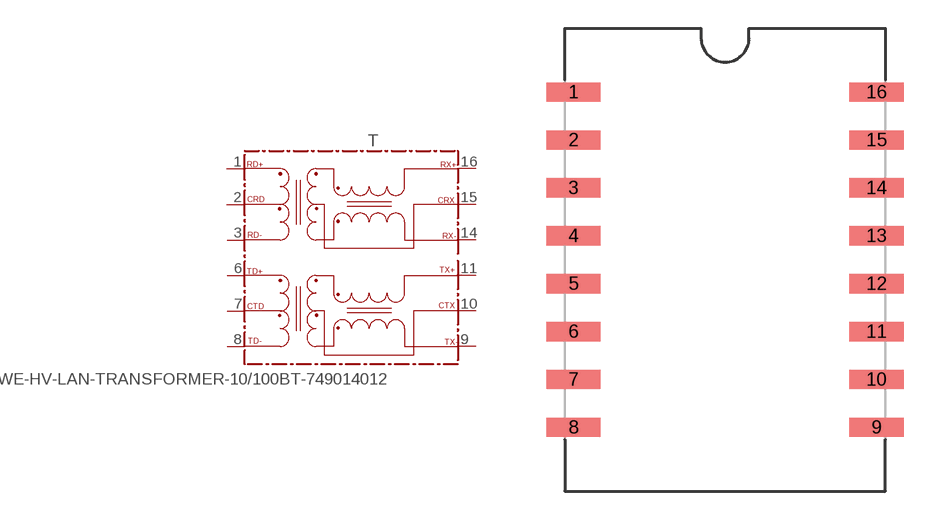
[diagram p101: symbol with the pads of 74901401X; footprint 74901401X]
Designator prefix T

## WE-HV-LAN-TRANSFORMER-10/100BT-749014012 (COMPANY-URL: http://www.we-online.de; CREATED-BY: Christin Zierenner; CREATED-DATE: July 2012; DATASHEET-URL: http://katalog.we-online.de/kataloge/eisos/media/pdf/749014012.pdf; MANUFACTURER: Würth Elektronik eiSos GmbH)  [74901401X]
1  RD+
2  CRD
3  RD-
6  TD+
7  CTD
8  TD-
9  TX-
10  CTX
11  TX+
14  RX-
15  CRX
16  RX+

## Footprint 74901401X (pad centres in mm)
MAX Height=10.85 mm
smd 2.87 x 1.02: 1 -8.03,8.89; 2 -8.03,6.35; 3 -8.03,3.81; 4 -8.03,1.27; 5 -8.03,-1.27; 6 -8.03,-3.81; 7 -8.03,-6.35; 8 -8.03,-8.89; 9 8.03,-8.89; 10 8.03,-6.35; 11 8.03,-3.81; 12 8.03,-1.27; 13 8.03,1.27; 14 8.03,3.81; 15 8.03,6.35; 16 8.03,8.89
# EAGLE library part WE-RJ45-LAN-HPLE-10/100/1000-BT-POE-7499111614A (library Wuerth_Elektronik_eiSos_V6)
Order Code 7499111614A Design THT xBase-T 10/100/1000 Base-T Ports 1x1 Application Standard HPLE Tab Position Up LED (Left-Right) GREEN/ORANGE-YELLOW EMI Fingers YES

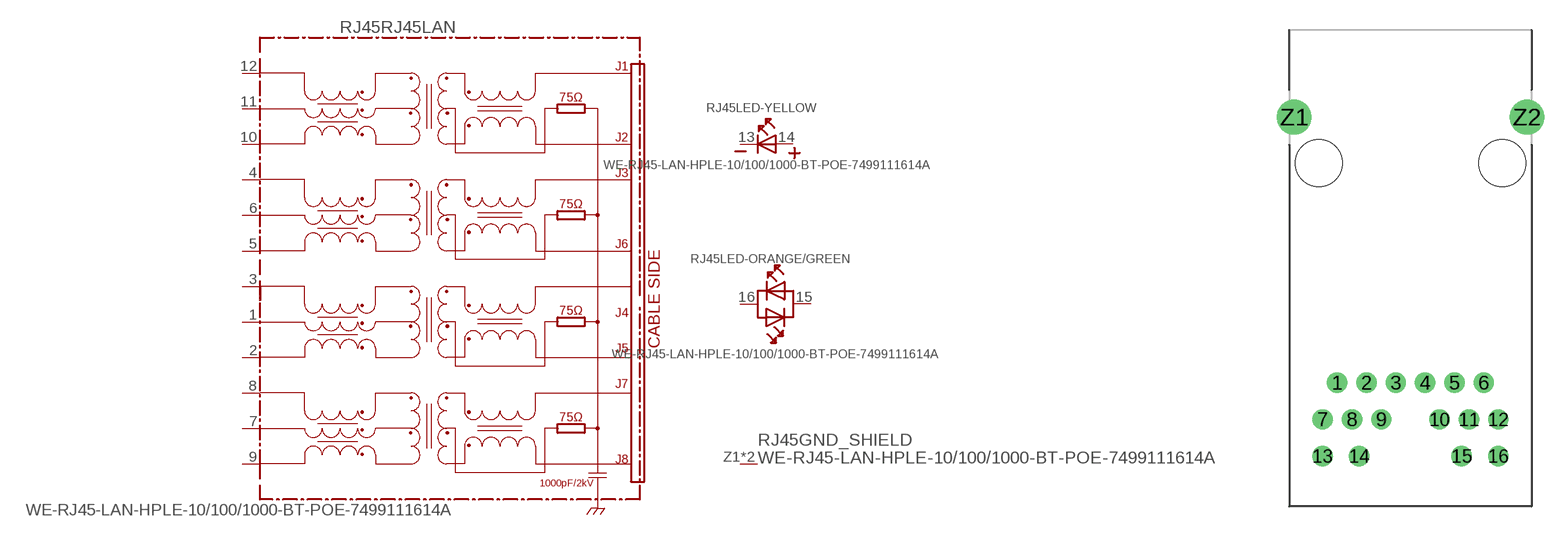
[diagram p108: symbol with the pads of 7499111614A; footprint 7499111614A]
Designator prefix RJ45; gates RJ45LAN=7499111614A LED-YELLOW=LED-2PIN LED-ORANGE/GREEN=LED-DUAL GND_SHIELD=GND_PIN

## WE-RJ45-LAN-HPLE-10/100/1000-BT-POE-7499111614A (COMPANY-URL: http://www.we-online.de; CREATED-BY: Christin Zierenner; CREATED-DATE: AUG 2012; DATASHEET-URL: http://katalog.we-online.de/kataloge/eisos/media/pdf/7499111614A.pdf; MANUFACTURER: Würth Elektronik eiSos GmbH)  [7499111614A]
1  RJ45LAN:1
2  RJ45LAN:2
3  RJ45LAN:3
4  RJ45LAN:4
5  RJ45LAN:5
6  RJ45LAN:6
7  RJ45LAN:7
8  RJ45LAN:8
9  RJ45LAN:9
10  RJ45LAN:10
11  RJ45LAN:11
12  RJ45LAN:12
13  LED-YELLOW:K
14  LED-YELLOW:A
15  LED-ORANGE/GREEN:AK2
16  LED-ORANGE/GREEN:AK1
Z1  GND_SHIELD:P$1  pwr
Z2  GND_SHIELD:P$1  pwr

## Footprint 7499111614A (pad centres in mm)
MAX HEIGHT=13.87mm PORTS----1X1 LED --YES
drill 0.9: 1 -5.075,-15.24; 2 -3.045,-15.24; 3 -1.015,-15.24; 4 1.015,-15.24; 5 3.045,-15.24; 6 5.075,-15.24; 7 -6.085,-17.78; 8 -4.055,-17.78; 9 -2.025,-17.78; 10 2.025,-17.78; 11 4.055,-17.78; 12 6.085,-17.78; 13 -6.09,-20.32; 14 -3.55,-20.32; 15 3.55,-20.32; 16 6.09,-20.32
drill 1.6: Z1 -8.065,3.18; Z2 8.065,3.18
hole 3.25 at 6.35,0
hole 3.25 at -6.35,0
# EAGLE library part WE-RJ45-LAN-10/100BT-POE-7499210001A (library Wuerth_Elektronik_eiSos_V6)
Order Code 7499210001A Design THT xBase-T 10/100 Base-T PoE Ports 1x1 Application PoE Tab Position UP LED (Left-Right) NONE EMI Fingers No

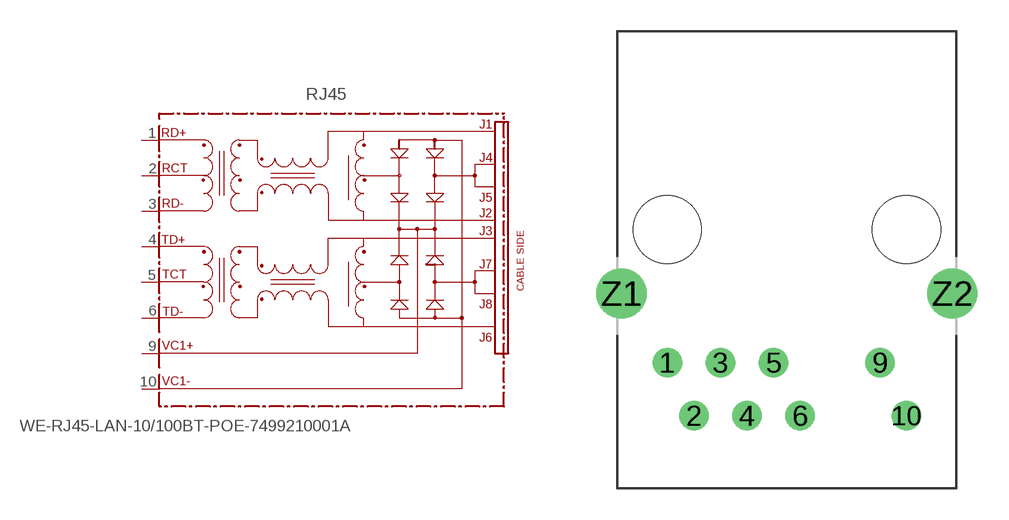
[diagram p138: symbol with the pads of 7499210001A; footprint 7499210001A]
Designator prefix RJ45

## WE-RJ45-LAN-10/100BT-POE-7499210001A (COMPANY-URL: http://www.we-online.de; CREATED-BY: Christin Zierenner; CREATED-DATE: AUG 2012; DATASHEET-URL: http://katalog.we-online.de/kataloge/eisos/media/pdf/7499210001A.pdf; MANUFACTURER: Würth Elektronik eiSos GmbH)  [7499210001A]
1  RD+
2  RCT
3  RD-
4  TD+
5  TCT
6  TD-
9  VC1+  pwr
10  VC1-  pwr

## Footprint 7499210001A (pad centres in mm)
MAX HEIGHT=13.74mm PORTS----1X1 LED --NO
drill 0.9: 1 -5.715,-5.08; 2 -4.445,-7.62; 3 -3.175,-5.08; 4 -1.905,-7.62; 5 -0.635,-5.08; 6 0.635,-7.62; 9 4.445,-5.08; 10 5.715,-7.62
drill 1.6: Z1 -7.9,-1.78; Z2 7.9,-1.78
hole 3.25 at 5.715,1.27
hole 3.25 at -5.715,1.27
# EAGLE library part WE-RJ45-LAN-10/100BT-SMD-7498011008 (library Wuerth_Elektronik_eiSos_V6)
Order Code 7498011008 Design SMD xBase-T 10/100 Base-T Ports 1x1 Application Standard Tab Position Down LED (Left-Right) None EMI Fingers Yes

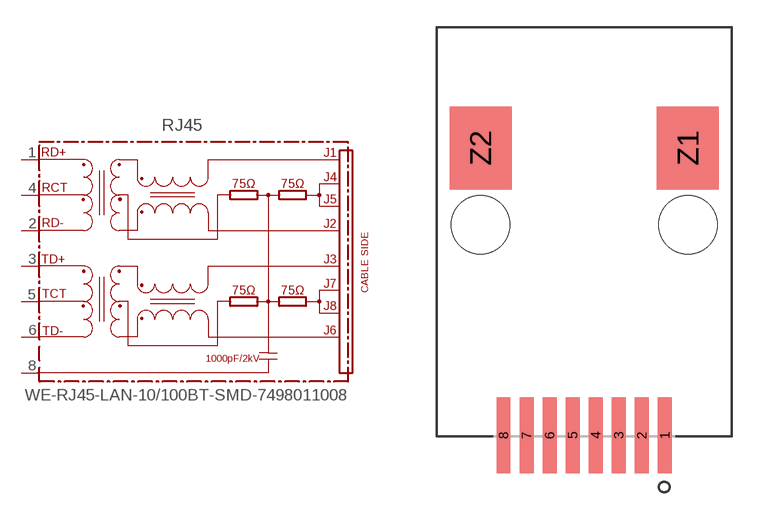
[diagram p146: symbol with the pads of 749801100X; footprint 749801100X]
Designator prefix RJ45

## WE-RJ45-LAN-10/100BT-SMD-7498011008 (COMPANY-URL: http://www.we-online.de; CREATED-BY: Christin Zierenner; CREATED-DATE: AUG 2012; DATASHEET-URL: http://katalog.we-online.de/kataloge/eisos/media/pdf/7498011008.pdf; MANUFACTURER: Würth Elektronik eiSos GmbH)  [749801100X]
1  RD+
2  RD-
3  TD+
4  RCT
5  TCT
6  TD-
8  SH  pwr

## Footprint 749801100X (pad centres in mm)
MAX HEIGHT=13.60mm PORTS----1X1 LED --No
smd 0.76 x 4.18: 1 4.445,-11.61; 2 3.175,-11.61; 3 1.905,-11.61; 4 0.635,-11.61; 5 -0.635,-11.61; 6 -1.905,-11.61; 7 -3.175,-11.61; 8 -4.445,-11.61
smd 3.42 x 4.58: Z1 5.715,4.24; Z2 -5.715,4.24
hole 3.22 at -5.715,0
hole 3.22 at 5.715,0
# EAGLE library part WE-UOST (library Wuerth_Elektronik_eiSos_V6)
Universal Offline Standard Transformers WE-UOST - Approximate 1% stray inductance for symmetrical interference suppression -- Input voltage range 85-265VAC (125-375VDC) -- Output power 12-16W -- designed to comply with EN61558-2-16: reinforced insulation -- creepage and clearance distance > 6.5 mm --Insulation test voltage 4kV(AC) -- For SMD assembly

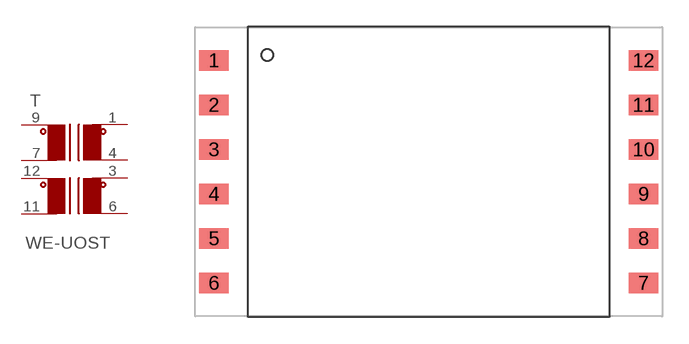
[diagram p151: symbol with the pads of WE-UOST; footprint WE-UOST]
Designator prefix T

## WE-UOSTSCH-1 (COMPANY-URL: http://www.we-online.de; CREATED-BY: Christin Otto; CREATED-DATE: MAR 2013; DATASHEET-URL: http://katalog.we-online.de/en/pbs/WE-UOST?m=t&sq=uost&sp=&sp=http%3A%2F%2Fwww.we-online.de%2Fweb%2Fen%2Felectronic_components%2Fsearchpage_PBS.php%3Fsearch%3DUOST; MANUFACTURER: Würth Elektronik eiSos GmbH)  [WE-UOST]
1  1  pas
3  3  pas
4  4  pas
6  6  pas
7  7  pas
9  9  pas
11  11  pas
12  12  pas

## WE-UOSTSCH-2 (COMPANY-URL: http://www.we-online.de; CREATED-BY: Christin Zierenner; CREATED-DATE: JAN 2013; DATASHEET-URL: http://katalog.we-online.de/en/pbs/WE-UOST?m=t&sq=uost&sp=&sp=http%3A%2F%2Fwww.we-online.de%2Fweb%2Fen%2Felectronic_components%2Fsearchpage_PBS.php%3Fsearch%3DUOST; MANUFACTURER: Würth Elektronik eiSos GmbH)  [WE-UOST]
1  1  pas
2  4  pas
3  3  pas
4  3  pas
5  6  pas
6  6  pas
7  7  pas
9  9  pas
11  11  pas
12  12  pas

## Footprint WE-UOST (pad centres in mm)
Universal Offline Standard Transformers WE-UOST
smd 1.7 x 1.17: 1 -12.265,6.35; 2 -12.265,3.81; 3 -12.265,1.27; 4 -12.265,-1.27; 5 -12.265,-3.81; 6 -12.265,-6.35; 7 12.265,-6.35; 8 12.265,-3.81; 9 12.265,-1.27; 10 12.265,1.27; 11 12.265,3.81; 12 12.265,6.35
